VERSION 5.7 ;
  NOWIREEXTENSIONATPIN ON ;
  DIVIDERCHAR "/" ;
  BUSBITCHARS "[]" ;
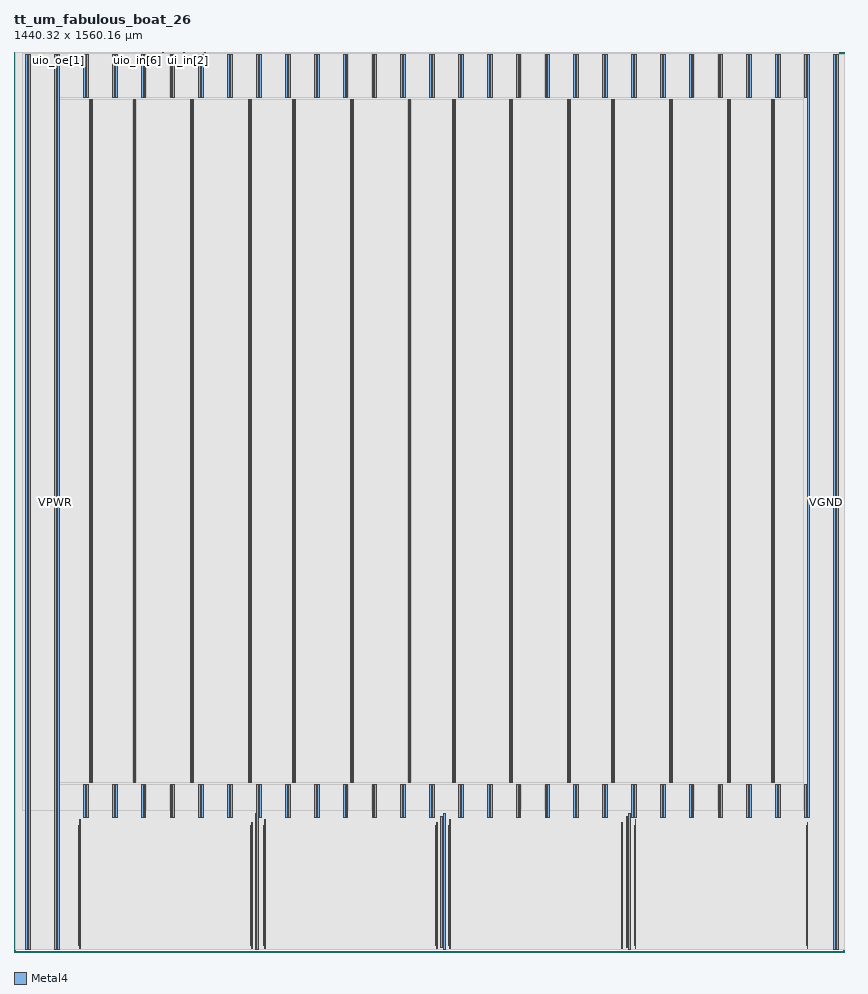
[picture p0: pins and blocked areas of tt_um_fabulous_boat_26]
MACRO tt_um_fabulous_boat_26
  CLASS BLOCK ;
  FOREIGN tt_um_fabulous_boat_26 ;
  ORIGIN 0.000 0.000 ;
  SIZE 1440.320 BY 1560.160 ;
  PIN VGND
    DIRECTION INOUT ;
    USE GROUND ;
    PORT
      LAYER Metal4 ;
        RECT 134.180 1403.360 135.780 1477.840 ;
    END
    PORT
      LAYER Metal4 ;
        RECT 134.180 1144.640 135.780 1403.360 ;
    END
    PORT
      LAYER Metal4 ;
        RECT 134.180 885.920 135.780 1144.640 ;
    END
    PORT
      LAYER Metal4 ;
        RECT 134.180 627.200 135.780 885.920 ;
    END
    PORT
      LAYER Metal4 ;
        RECT 134.180 368.480 135.780 627.200 ;
    END
    PORT
      LAYER Metal4 ;
        RECT 134.180 294.000 135.780 368.480 ;
    END
    PORT
      LAYER Metal4 ;
        RECT 209.780 1403.360 211.380 1477.840 ;
    END
    PORT
      LAYER Metal4 ;
        RECT 309.780 1403.360 311.380 1477.840 ;
    END
    PORT
      LAYER Metal4 ;
        RECT 409.780 1403.360 411.380 1477.840 ;
    END
    PORT
      LAYER Metal4 ;
        RECT 209.780 1144.640 211.380 1403.360 ;
    END
    PORT
      LAYER Metal4 ;
        RECT 309.780 1144.640 311.380 1403.360 ;
    END
    PORT
      LAYER Metal4 ;
        RECT 409.780 1144.640 411.380 1403.360 ;
    END
    PORT
      LAYER Metal4 ;
        RECT 209.780 885.920 211.380 1144.640 ;
    END
    PORT
      LAYER Metal4 ;
        RECT 309.780 885.920 311.380 1144.640 ;
    END
    PORT
      LAYER Metal4 ;
        RECT 409.780 885.920 411.380 1144.640 ;
    END
    PORT
      LAYER Metal4 ;
        RECT 209.780 627.200 211.380 885.920 ;
    END
    PORT
      LAYER Metal4 ;
        RECT 309.780 627.200 311.380 885.920 ;
    END
    PORT
      LAYER Metal4 ;
        RECT 409.780 627.200 411.380 885.920 ;
    END
    PORT
      LAYER Metal4 ;
        RECT 209.780 368.480 211.380 627.200 ;
    END
    PORT
      LAYER Metal4 ;
        RECT 309.780 368.480 311.380 627.200 ;
    END
    PORT
      LAYER Metal4 ;
        RECT 409.780 368.480 411.380 627.200 ;
    END
    PORT
      LAYER Metal4 ;
        RECT 209.780 294.000 211.380 368.480 ;
    END
    PORT
      LAYER Metal4 ;
        RECT 309.780 294.000 311.380 368.480 ;
    END
    PORT
      LAYER Metal4 ;
        RECT 409.780 294.000 411.380 368.480 ;
    END
    PORT
      LAYER Metal4 ;
        RECT 486.420 1403.360 488.020 1477.840 ;
    END
    PORT
      LAYER Metal4 ;
        RECT 586.420 1403.360 588.020 1477.840 ;
    END
    PORT
      LAYER Metal4 ;
        RECT 686.420 1403.360 688.020 1477.840 ;
    END
    PORT
      LAYER Metal4 ;
        RECT 486.420 1144.640 488.020 1403.360 ;
    END
    PORT
      LAYER Metal4 ;
        RECT 586.420 1144.640 588.020 1403.360 ;
    END
    PORT
      LAYER Metal4 ;
        RECT 686.420 1144.640 688.020 1403.360 ;
    END
    PORT
      LAYER Metal4 ;
        RECT 486.420 885.920 488.020 1144.640 ;
    END
    PORT
      LAYER Metal4 ;
        RECT 586.420 885.920 588.020 1144.640 ;
    END
    PORT
      LAYER Metal4 ;
        RECT 686.420 885.920 688.020 1144.640 ;
    END
    PORT
      LAYER Metal4 ;
        RECT 486.420 627.200 488.020 885.920 ;
    END
    PORT
      LAYER Metal4 ;
        RECT 586.420 627.200 588.020 885.920 ;
    END
    PORT
      LAYER Metal4 ;
        RECT 686.420 627.200 688.020 885.920 ;
    END
    PORT
      LAYER Metal4 ;
        RECT 486.420 368.480 488.020 627.200 ;
    END
    PORT
      LAYER Metal4 ;
        RECT 586.420 368.480 588.020 627.200 ;
    END
    PORT
      LAYER Metal4 ;
        RECT 686.420 368.480 688.020 627.200 ;
    END
    PORT
      LAYER Metal4 ;
        RECT 486.420 294.000 488.020 368.480 ;
    END
    PORT
      LAYER Metal4 ;
        RECT 586.420 294.000 588.020 368.480 ;
    END
    PORT
      LAYER Metal4 ;
        RECT 686.420 294.000 688.020 368.480 ;
    END
    PORT
      LAYER Metal4 ;
        RECT 763.060 1403.360 764.660 1477.840 ;
    END
    PORT
      LAYER Metal4 ;
        RECT 863.060 1403.360 864.660 1477.840 ;
    END
    PORT
      LAYER Metal4 ;
        RECT 963.060 1403.360 964.660 1477.840 ;
    END
    PORT
      LAYER Metal4 ;
        RECT 763.060 1144.640 764.660 1403.360 ;
    END
    PORT
      LAYER Metal4 ;
        RECT 863.060 1144.640 864.660 1403.360 ;
    END
    PORT
      LAYER Metal4 ;
        RECT 963.060 1144.640 964.660 1403.360 ;
    END
    PORT
      LAYER Metal4 ;
        RECT 763.060 885.920 764.660 1144.640 ;
    END
    PORT
      LAYER Metal4 ;
        RECT 863.060 885.920 864.660 1144.640 ;
    END
    PORT
      LAYER Metal4 ;
        RECT 963.060 885.920 964.660 1144.640 ;
    END
    PORT
      LAYER Metal4 ;
        RECT 763.060 627.200 764.660 885.920 ;
    END
    PORT
      LAYER Metal4 ;
        RECT 863.060 627.200 864.660 885.920 ;
    END
    PORT
      LAYER Metal4 ;
        RECT 963.060 627.200 964.660 885.920 ;
    END
    PORT
      LAYER Metal4 ;
        RECT 763.060 368.480 764.660 627.200 ;
    END
    PORT
      LAYER Metal4 ;
        RECT 863.060 368.480 864.660 627.200 ;
    END
    PORT
      LAYER Metal4 ;
        RECT 963.060 368.480 964.660 627.200 ;
    END
    PORT
      LAYER Metal4 ;
        RECT 763.060 294.000 764.660 368.480 ;
    END
    PORT
      LAYER Metal4 ;
        RECT 863.060 294.000 864.660 368.480 ;
    END
    PORT
      LAYER Metal4 ;
        RECT 963.060 294.000 964.660 368.480 ;
    END
    PORT
      LAYER Metal4 ;
        RECT 1039.700 1403.360 1041.300 1477.840 ;
    END
    PORT
      LAYER Metal4 ;
        RECT 1139.700 1403.360 1141.300 1477.840 ;
    END
    PORT
      LAYER Metal4 ;
        RECT 1239.700 1403.360 1241.300 1477.840 ;
    END
    PORT
      LAYER Metal4 ;
        RECT 1039.700 1144.640 1041.300 1403.360 ;
    END
    PORT
      LAYER Metal4 ;
        RECT 1139.700 1144.640 1141.300 1403.360 ;
    END
    PORT
      LAYER Metal4 ;
        RECT 1239.700 1144.640 1241.300 1403.360 ;
    END
    PORT
      LAYER Metal4 ;
        RECT 1039.700 885.920 1041.300 1144.640 ;
    END
    PORT
      LAYER Metal4 ;
        RECT 1139.700 885.920 1141.300 1144.640 ;
    END
    PORT
      LAYER Metal4 ;
        RECT 1239.700 885.920 1241.300 1144.640 ;
    END
    PORT
      LAYER Metal4 ;
        RECT 1039.700 627.200 1041.300 885.920 ;
    END
    PORT
      LAYER Metal4 ;
        RECT 1139.700 627.200 1141.300 885.920 ;
    END
    PORT
      LAYER Metal4 ;
        RECT 1239.700 627.200 1241.300 885.920 ;
    END
    PORT
      LAYER Metal4 ;
        RECT 1039.700 368.480 1041.300 627.200 ;
    END
    PORT
      LAYER Metal4 ;
        RECT 1139.700 368.480 1141.300 627.200 ;
    END
    PORT
      LAYER Metal4 ;
        RECT 1239.700 368.480 1241.300 627.200 ;
    END
    PORT
      LAYER Metal4 ;
        RECT 1039.700 294.000 1041.300 368.480 ;
    END
    PORT
      LAYER Metal4 ;
        RECT 1139.700 294.000 1141.300 368.480 ;
    END
    PORT
      LAYER Metal4 ;
        RECT 1239.700 294.000 1241.300 368.480 ;
    END
    PORT
      LAYER Metal4 ;
        RECT 1316.340 1403.360 1317.940 1477.840 ;
    END
    PORT
      LAYER Metal4 ;
        RECT 1316.340 1144.640 1317.940 1403.360 ;
    END
    PORT
      LAYER Metal4 ;
        RECT 1316.340 885.920 1317.940 1144.640 ;
    END
    PORT
      LAYER Metal4 ;
        RECT 1316.340 627.200 1317.940 885.920 ;
    END
    PORT
      LAYER Metal4 ;
        RECT 1316.340 368.480 1317.940 627.200 ;
    END
    PORT
      LAYER Metal4 ;
        RECT 1316.340 294.000 1317.940 368.480 ;
    END
    PORT
      LAYER Metal4 ;
        RECT 25.540 3.620 28.740 1556.540 ;
    END
    PORT
      LAYER Metal4 ;
        RECT 75.540 3.620 78.740 1556.540 ;
    END
    PORT
      LAYER Metal4 ;
        RECT 125.540 233.610 128.740 289.890 ;
    END
    PORT
      LAYER Metal4 ;
        RECT 125.540 1481.950 128.740 1556.540 ;
    END
    PORT
      LAYER Metal4 ;
        RECT 175.540 233.610 178.740 289.890 ;
    END
    PORT
      LAYER Metal4 ;
        RECT 175.540 1481.950 178.740 1556.540 ;
    END
    PORT
      LAYER Metal4 ;
        RECT 225.540 233.610 228.740 289.890 ;
    END
    PORT
      LAYER Metal4 ;
        RECT 225.540 1481.950 228.740 1556.540 ;
    END
    PORT
      LAYER Metal4 ;
        RECT 275.540 233.610 278.740 289.890 ;
    END
    PORT
      LAYER Metal4 ;
        RECT 275.540 1481.950 278.740 1556.540 ;
    END
    PORT
      LAYER Metal4 ;
        RECT 325.540 233.610 328.740 289.890 ;
    END
    PORT
      LAYER Metal4 ;
        RECT 325.540 1481.950 328.740 1556.540 ;
    END
    PORT
      LAYER Metal4 ;
        RECT 375.540 233.610 378.740 289.890 ;
    END
    PORT
      LAYER Metal4 ;
        RECT 375.540 1481.950 378.740 1556.540 ;
    END
    PORT
      LAYER Metal4 ;
        RECT 425.540 233.610 428.740 289.890 ;
    END
    PORT
      LAYER Metal4 ;
        RECT 425.540 1481.950 428.740 1556.540 ;
    END
    PORT
      LAYER Metal4 ;
        RECT 475.540 233.610 478.740 289.890 ;
    END
    PORT
      LAYER Metal4 ;
        RECT 475.540 1481.950 478.740 1556.540 ;
    END
    PORT
      LAYER Metal4 ;
        RECT 525.540 233.610 528.740 289.890 ;
    END
    PORT
      LAYER Metal4 ;
        RECT 525.540 1481.950 528.740 1556.540 ;
    END
    PORT
      LAYER Metal4 ;
        RECT 575.540 233.610 578.740 289.890 ;
    END
    PORT
      LAYER Metal4 ;
        RECT 575.540 1481.950 578.740 1556.540 ;
    END
    PORT
      LAYER Metal4 ;
        RECT 625.540 233.610 628.740 289.890 ;
    END
    PORT
      LAYER Metal4 ;
        RECT 625.540 1481.950 628.740 1556.540 ;
    END
    PORT
      LAYER Metal4 ;
        RECT 675.540 233.610 678.740 289.890 ;
    END
    PORT
      LAYER Metal4 ;
        RECT 675.540 1481.950 678.740 1556.540 ;
    END
    PORT
      LAYER Metal4 ;
        RECT 725.540 233.610 728.740 289.890 ;
    END
    PORT
      LAYER Metal4 ;
        RECT 725.540 1481.950 728.740 1556.540 ;
    END
    PORT
      LAYER Metal4 ;
        RECT 775.540 233.610 778.740 289.890 ;
    END
    PORT
      LAYER Metal4 ;
        RECT 775.540 1481.950 778.740 1556.540 ;
    END
    PORT
      LAYER Metal4 ;
        RECT 825.540 233.610 828.740 289.890 ;
    END
    PORT
      LAYER Metal4 ;
        RECT 825.540 1481.950 828.740 1556.540 ;
    END
    PORT
      LAYER Metal4 ;
        RECT 875.540 233.610 878.740 289.890 ;
    END
    PORT
      LAYER Metal4 ;
        RECT 875.540 1481.950 878.740 1556.540 ;
    END
    PORT
      LAYER Metal4 ;
        RECT 925.540 233.610 928.740 289.890 ;
    END
    PORT
      LAYER Metal4 ;
        RECT 925.540 1481.950 928.740 1556.540 ;
    END
    PORT
      LAYER Metal4 ;
        RECT 975.540 233.610 978.740 289.890 ;
    END
    PORT
      LAYER Metal4 ;
        RECT 975.540 1481.950 978.740 1556.540 ;
    END
    PORT
      LAYER Metal4 ;
        RECT 1025.540 233.610 1028.740 289.890 ;
    END
    PORT
      LAYER Metal4 ;
        RECT 1025.540 1481.950 1028.740 1556.540 ;
    END
    PORT
      LAYER Metal4 ;
        RECT 1075.540 233.610 1078.740 289.890 ;
    END
    PORT
      LAYER Metal4 ;
        RECT 1075.540 1481.950 1078.740 1556.540 ;
    END
    PORT
      LAYER Metal4 ;
        RECT 1125.540 233.610 1128.740 289.890 ;
    END
    PORT
      LAYER Metal4 ;
        RECT 1125.540 1481.950 1128.740 1556.540 ;
    END
    PORT
      LAYER Metal4 ;
        RECT 1175.540 233.610 1178.740 289.890 ;
    END
    PORT
      LAYER Metal4 ;
        RECT 1175.540 1481.950 1178.740 1556.540 ;
    END
    PORT
      LAYER Metal4 ;
        RECT 1225.540 233.610 1228.740 289.890 ;
    END
    PORT
      LAYER Metal4 ;
        RECT 1225.540 1481.950 1228.740 1556.540 ;
    END
    PORT
      LAYER Metal4 ;
        RECT 1275.540 233.610 1278.740 289.890 ;
    END
    PORT
      LAYER Metal4 ;
        RECT 1275.540 1481.950 1278.740 1556.540 ;
    END
    PORT
      LAYER Metal4 ;
        RECT 1325.540 233.610 1328.740 289.890 ;
    END
    PORT
      LAYER Metal4 ;
        RECT 1325.540 1481.950 1328.740 1556.540 ;
    END
    PORT
      LAYER Metal4 ;
        RECT 1375.540 233.610 1378.740 1556.540 ;
    END
    PORT
      LAYER Metal4 ;
        RECT 1425.540 3.620 1428.740 1556.540 ;
    END
    PORT
      LAYER Metal4 ;
        RECT 1373.300 10.615 1374.660 220.100 ;
    END
    PORT
      LAYER Metal4 ;
        RECT 1075.000 10.600 1076.360 220.110 ;
    END
    PORT
      LAYER Metal4 ;
        RECT 1052.300 10.615 1053.660 220.100 ;
    END
    PORT
      LAYER Metal4 ;
        RECT 754.000 10.600 755.360 220.110 ;
    END
    PORT
      LAYER Metal4 ;
        RECT 731.300 10.615 732.660 220.100 ;
    END
    PORT
      LAYER Metal4 ;
        RECT 433.000 10.600 434.360 220.110 ;
    END
    PORT
      LAYER Metal4 ;
        RECT 410.300 10.615 411.660 220.100 ;
    END
    PORT
      LAYER Metal4 ;
        RECT 112.000 10.600 113.360 220.110 ;
    END
    PORT
      LAYER Metal4 ;
        RECT 1066.040 3.620 1069.240 239.420 ;
    END
    PORT
      LAYER Metal4 ;
        RECT 745.160 3.620 748.360 239.420 ;
    END
    PORT
      LAYER Metal4 ;
        RECT 418.360 3.620 419.960 239.420 ;
    END
  END VGND
  PIN VPWR
    DIRECTION INOUT ;
    USE POWER ;
    PORT
      LAYER Metal4 ;
        RECT 130.880 1403.360 132.480 1477.840 ;
    END
    PORT
      LAYER Metal4 ;
        RECT 130.880 1144.640 132.480 1403.360 ;
    END
    PORT
      LAYER Metal4 ;
        RECT 130.880 885.920 132.480 1144.640 ;
    END
    PORT
      LAYER Metal4 ;
        RECT 130.880 627.200 132.480 885.920 ;
    END
    PORT
      LAYER Metal4 ;
        RECT 130.880 368.480 132.480 627.200 ;
    END
    PORT
      LAYER Metal4 ;
        RECT 130.880 294.000 132.480 368.480 ;
    END
    PORT
      LAYER Metal4 ;
        RECT 206.480 1403.360 208.080 1477.840 ;
    END
    PORT
      LAYER Metal4 ;
        RECT 306.480 1403.360 308.080 1477.840 ;
    END
    PORT
      LAYER Metal4 ;
        RECT 406.480 1403.360 408.080 1477.840 ;
    END
    PORT
      LAYER Metal4 ;
        RECT 206.480 1144.640 208.080 1403.360 ;
    END
    PORT
      LAYER Metal4 ;
        RECT 306.480 1144.640 308.080 1403.360 ;
    END
    PORT
      LAYER Metal4 ;
        RECT 406.480 1144.640 408.080 1403.360 ;
    END
    PORT
      LAYER Metal4 ;
        RECT 206.480 885.920 208.080 1144.640 ;
    END
    PORT
      LAYER Metal4 ;
        RECT 306.480 885.920 308.080 1144.640 ;
    END
    PORT
      LAYER Metal4 ;
        RECT 406.480 885.920 408.080 1144.640 ;
    END
    PORT
      LAYER Metal4 ;
        RECT 206.480 627.200 208.080 885.920 ;
    END
    PORT
      LAYER Metal4 ;
        RECT 306.480 627.200 308.080 885.920 ;
    END
    PORT
      LAYER Metal4 ;
        RECT 406.480 627.200 408.080 885.920 ;
    END
    PORT
      LAYER Metal4 ;
        RECT 206.480 368.480 208.080 627.200 ;
    END
    PORT
      LAYER Metal4 ;
        RECT 306.480 368.480 308.080 627.200 ;
    END
    PORT
      LAYER Metal4 ;
        RECT 406.480 368.480 408.080 627.200 ;
    END
    PORT
      LAYER Metal4 ;
        RECT 206.480 294.000 208.080 368.480 ;
    END
    PORT
      LAYER Metal4 ;
        RECT 306.480 294.000 308.080 368.480 ;
    END
    PORT
      LAYER Metal4 ;
        RECT 406.480 294.000 408.080 368.480 ;
    END
    PORT
      LAYER Metal4 ;
        RECT 483.120 1403.360 484.720 1477.840 ;
    END
    PORT
      LAYER Metal4 ;
        RECT 583.120 1403.360 584.720 1477.840 ;
    END
    PORT
      LAYER Metal4 ;
        RECT 683.120 1403.360 684.720 1477.840 ;
    END
    PORT
      LAYER Metal4 ;
        RECT 483.120 1144.640 484.720 1403.360 ;
    END
    PORT
      LAYER Metal4 ;
        RECT 583.120 1144.640 584.720 1403.360 ;
    END
    PORT
      LAYER Metal4 ;
        RECT 683.120 1144.640 684.720 1403.360 ;
    END
    PORT
      LAYER Metal4 ;
        RECT 483.120 885.920 484.720 1144.640 ;
    END
    PORT
      LAYER Metal4 ;
        RECT 583.120 885.920 584.720 1144.640 ;
    END
    PORT
      LAYER Metal4 ;
        RECT 683.120 885.920 684.720 1144.640 ;
    END
    PORT
      LAYER Metal4 ;
        RECT 483.120 627.200 484.720 885.920 ;
    END
    PORT
      LAYER Metal4 ;
        RECT 583.120 627.200 584.720 885.920 ;
    END
    PORT
      LAYER Metal4 ;
        RECT 683.120 627.200 684.720 885.920 ;
    END
    PORT
      LAYER Metal4 ;
        RECT 483.120 368.480 484.720 627.200 ;
    END
    PORT
      LAYER Metal4 ;
        RECT 583.120 368.480 584.720 627.200 ;
    END
    PORT
      LAYER Metal4 ;
        RECT 683.120 368.480 684.720 627.200 ;
    END
    PORT
      LAYER Metal4 ;
        RECT 483.120 294.000 484.720 368.480 ;
    END
    PORT
      LAYER Metal4 ;
        RECT 583.120 294.000 584.720 368.480 ;
    END
    PORT
      LAYER Metal4 ;
        RECT 683.120 294.000 684.720 368.480 ;
    END
    PORT
      LAYER Metal4 ;
        RECT 759.760 1403.360 761.360 1477.840 ;
    END
    PORT
      LAYER Metal4 ;
        RECT 859.760 1403.360 861.360 1477.840 ;
    END
    PORT
      LAYER Metal4 ;
        RECT 959.760 1403.360 961.360 1477.840 ;
    END
    PORT
      LAYER Metal4 ;
        RECT 759.760 1144.640 761.360 1403.360 ;
    END
    PORT
      LAYER Metal4 ;
        RECT 859.760 1144.640 861.360 1403.360 ;
    END
    PORT
      LAYER Metal4 ;
        RECT 959.760 1144.640 961.360 1403.360 ;
    END
    PORT
      LAYER Metal4 ;
        RECT 759.760 885.920 761.360 1144.640 ;
    END
    PORT
      LAYER Metal4 ;
        RECT 859.760 885.920 861.360 1144.640 ;
    END
    PORT
      LAYER Metal4 ;
        RECT 959.760 885.920 961.360 1144.640 ;
    END
    PORT
      LAYER Metal4 ;
        RECT 759.760 627.200 761.360 885.920 ;
    END
    PORT
      LAYER Metal4 ;
        RECT 859.760 627.200 861.360 885.920 ;
    END
    PORT
      LAYER Metal4 ;
        RECT 959.760 627.200 961.360 885.920 ;
    END
    PORT
      LAYER Metal4 ;
        RECT 759.760 368.480 761.360 627.200 ;
    END
    PORT
      LAYER Metal4 ;
        RECT 859.760 368.480 861.360 627.200 ;
    END
    PORT
      LAYER Metal4 ;
        RECT 959.760 368.480 961.360 627.200 ;
    END
    PORT
      LAYER Metal4 ;
        RECT 759.760 294.000 761.360 368.480 ;
    END
    PORT
      LAYER Metal4 ;
        RECT 859.760 294.000 861.360 368.480 ;
    END
    PORT
      LAYER Metal4 ;
        RECT 959.760 294.000 961.360 368.480 ;
    END
    PORT
      LAYER Metal4 ;
        RECT 1036.400 1403.360 1038.000 1477.840 ;
    END
    PORT
      LAYER Metal4 ;
        RECT 1136.400 1403.360 1138.000 1477.840 ;
    END
    PORT
      LAYER Metal4 ;
        RECT 1236.400 1403.360 1238.000 1477.840 ;
    END
    PORT
      LAYER Metal4 ;
        RECT 1036.400 1144.640 1038.000 1403.360 ;
    END
    PORT
      LAYER Metal4 ;
        RECT 1136.400 1144.640 1138.000 1403.360 ;
    END
    PORT
      LAYER Metal4 ;
        RECT 1236.400 1144.640 1238.000 1403.360 ;
    END
    PORT
      LAYER Metal4 ;
        RECT 1036.400 885.920 1038.000 1144.640 ;
    END
    PORT
      LAYER Metal4 ;
        RECT 1136.400 885.920 1138.000 1144.640 ;
    END
    PORT
      LAYER Metal4 ;
        RECT 1236.400 885.920 1238.000 1144.640 ;
    END
    PORT
      LAYER Metal4 ;
        RECT 1036.400 627.200 1038.000 885.920 ;
    END
    PORT
      LAYER Metal4 ;
        RECT 1136.400 627.200 1138.000 885.920 ;
    END
    PORT
      LAYER Metal4 ;
        RECT 1236.400 627.200 1238.000 885.920 ;
    END
    PORT
      LAYER Metal4 ;
        RECT 1036.400 368.480 1038.000 627.200 ;
    END
    PORT
      LAYER Metal4 ;
        RECT 1136.400 368.480 1138.000 627.200 ;
    END
    PORT
      LAYER Metal4 ;
        RECT 1236.400 368.480 1238.000 627.200 ;
    END
    PORT
      LAYER Metal4 ;
        RECT 1036.400 294.000 1038.000 368.480 ;
    END
    PORT
      LAYER Metal4 ;
        RECT 1136.400 294.000 1138.000 368.480 ;
    END
    PORT
      LAYER Metal4 ;
        RECT 1236.400 294.000 1238.000 368.480 ;
    END
    PORT
      LAYER Metal4 ;
        RECT 1313.040 1403.360 1314.640 1477.840 ;
    END
    PORT
      LAYER Metal4 ;
        RECT 1313.040 1144.640 1314.640 1403.360 ;
    END
    PORT
      LAYER Metal4 ;
        RECT 1313.040 885.920 1314.640 1144.640 ;
    END
    PORT
      LAYER Metal4 ;
        RECT 1313.040 627.200 1314.640 885.920 ;
    END
    PORT
      LAYER Metal4 ;
        RECT 1313.040 368.480 1314.640 627.200 ;
    END
    PORT
      LAYER Metal4 ;
        RECT 1313.040 294.000 1314.640 368.480 ;
    END
    PORT
      LAYER Metal4 ;
        RECT 20.640 3.620 23.840 1556.540 ;
    END
    PORT
      LAYER Metal4 ;
        RECT 70.640 3.620 73.840 1556.540 ;
    END
    PORT
      LAYER Metal4 ;
        RECT 120.640 233.610 123.840 289.890 ;
    END
    PORT
      LAYER Metal4 ;
        RECT 120.640 1481.950 123.840 1556.540 ;
    END
    PORT
      LAYER Metal4 ;
        RECT 170.640 233.610 173.840 289.890 ;
    END
    PORT
      LAYER Metal4 ;
        RECT 170.640 1481.950 173.840 1556.540 ;
    END
    PORT
      LAYER Metal4 ;
        RECT 220.640 233.610 223.840 289.890 ;
    END
    PORT
      LAYER Metal4 ;
        RECT 220.640 1481.950 223.840 1556.540 ;
    END
    PORT
      LAYER Metal4 ;
        RECT 270.640 233.610 273.840 289.890 ;
    END
    PORT
      LAYER Metal4 ;
        RECT 270.640 1481.950 273.840 1556.540 ;
    END
    PORT
      LAYER Metal4 ;
        RECT 320.640 233.610 323.840 289.890 ;
    END
    PORT
      LAYER Metal4 ;
        RECT 320.640 1481.950 323.840 1556.540 ;
    END
    PORT
      LAYER Metal4 ;
        RECT 370.640 233.610 373.840 289.890 ;
    END
    PORT
      LAYER Metal4 ;
        RECT 370.640 1481.950 373.840 1556.540 ;
    END
    PORT
      LAYER Metal4 ;
        RECT 420.640 3.620 423.840 289.890 ;
    END
    PORT
      LAYER Metal4 ;
        RECT 420.640 1481.950 423.840 1556.540 ;
    END
    PORT
      LAYER Metal4 ;
        RECT 470.640 233.610 473.840 289.890 ;
    END
    PORT
      LAYER Metal4 ;
        RECT 470.640 1481.950 473.840 1556.540 ;
    END
    PORT
      LAYER Metal4 ;
        RECT 520.640 233.610 523.840 289.890 ;
    END
    PORT
      LAYER Metal4 ;
        RECT 520.640 1481.950 523.840 1556.540 ;
    END
    PORT
      LAYER Metal4 ;
        RECT 570.640 233.610 573.840 289.890 ;
    END
    PORT
      LAYER Metal4 ;
        RECT 570.640 1481.950 573.840 1556.540 ;
    END
    PORT
      LAYER Metal4 ;
        RECT 620.640 233.610 623.840 289.890 ;
    END
    PORT
      LAYER Metal4 ;
        RECT 620.640 1481.950 623.840 1556.540 ;
    END
    PORT
      LAYER Metal4 ;
        RECT 670.640 233.610 673.840 289.890 ;
    END
    PORT
      LAYER Metal4 ;
        RECT 670.640 1481.950 673.840 1556.540 ;
    END
    PORT
      LAYER Metal4 ;
        RECT 720.640 233.610 723.840 289.890 ;
    END
    PORT
      LAYER Metal4 ;
        RECT 720.640 1481.950 723.840 1556.540 ;
    END
    PORT
      LAYER Metal4 ;
        RECT 770.640 233.610 773.840 289.890 ;
    END
    PORT
      LAYER Metal4 ;
        RECT 770.640 1481.950 773.840 1556.540 ;
    END
    PORT
      LAYER Metal4 ;
        RECT 820.640 233.610 823.840 289.890 ;
    END
    PORT
      LAYER Metal4 ;
        RECT 820.640 1481.950 823.840 1556.540 ;
    END
    PORT
      LAYER Metal4 ;
        RECT 870.640 233.610 873.840 289.890 ;
    END
    PORT
      LAYER Metal4 ;
        RECT 870.640 1481.950 873.840 1556.540 ;
    END
    PORT
      LAYER Metal4 ;
        RECT 920.640 233.610 923.840 289.890 ;
    END
    PORT
      LAYER Metal4 ;
        RECT 920.640 1481.950 923.840 1556.540 ;
    END
    PORT
      LAYER Metal4 ;
        RECT 970.640 233.610 973.840 289.890 ;
    END
    PORT
      LAYER Metal4 ;
        RECT 970.640 1481.950 973.840 1556.540 ;
    END
    PORT
      LAYER Metal4 ;
        RECT 1020.640 233.610 1023.840 289.890 ;
    END
    PORT
      LAYER Metal4 ;
        RECT 1020.640 1481.950 1023.840 1556.540 ;
    END
    PORT
      LAYER Metal4 ;
        RECT 1070.640 233.610 1073.840 289.890 ;
    END
    PORT
      LAYER Metal4 ;
        RECT 1070.640 1481.950 1073.840 1556.540 ;
    END
    PORT
      LAYER Metal4 ;
        RECT 1120.640 233.610 1123.840 289.890 ;
    END
    PORT
      LAYER Metal4 ;
        RECT 1120.640 1481.950 1123.840 1556.540 ;
    END
    PORT
      LAYER Metal4 ;
        RECT 1170.640 233.610 1173.840 289.890 ;
    END
    PORT
      LAYER Metal4 ;
        RECT 1170.640 1481.950 1173.840 1556.540 ;
    END
    PORT
      LAYER Metal4 ;
        RECT 1220.640 233.610 1223.840 289.890 ;
    END
    PORT
      LAYER Metal4 ;
        RECT 1220.640 1481.950 1223.840 1556.540 ;
    END
    PORT
      LAYER Metal4 ;
        RECT 1270.640 233.610 1273.840 289.890 ;
    END
    PORT
      LAYER Metal4 ;
        RECT 1270.640 1481.950 1273.840 1556.540 ;
    END
    PORT
      LAYER Metal4 ;
        RECT 1320.640 233.610 1323.840 289.890 ;
    END
    PORT
      LAYER Metal4 ;
        RECT 1320.640 1481.950 1323.840 1556.540 ;
    END
    PORT
      LAYER Metal4 ;
        RECT 1370.640 233.610 1373.840 289.890 ;
    END
    PORT
      LAYER Metal4 ;
        RECT 1370.640 1481.950 1373.840 1556.540 ;
    END
    PORT
      LAYER Metal4 ;
        RECT 1420.640 3.620 1423.840 1556.540 ;
    END
    PORT
      LAYER Metal4 ;
        RECT 1374.940 6.920 1376.300 224.540 ;
    END
    PORT
      LAYER Metal4 ;
        RECT 1076.640 6.920 1078.000 228.850 ;
    END
    PORT
      LAYER Metal4 ;
        RECT 1053.940 6.920 1055.300 224.540 ;
    END
    PORT
      LAYER Metal4 ;
        RECT 755.640 6.920 757.000 228.850 ;
    END
    PORT
      LAYER Metal4 ;
        RECT 732.940 6.920 734.300 224.540 ;
    END
    PORT
      LAYER Metal4 ;
        RECT 434.640 6.920 436.000 228.850 ;
    END
    PORT
      LAYER Metal4 ;
        RECT 411.940 6.920 413.300 224.540 ;
    END
    PORT
      LAYER Metal4 ;
        RECT 113.640 6.920 115.000 228.850 ;
    END
    PORT
      LAYER Metal4 ;
        RECT 1061.000 7.540 1064.200 235.500 ;
    END
    PORT
      LAYER Metal4 ;
        RECT 740.120 7.540 743.320 235.500 ;
    END
  END VPWR
  PIN clk
    DIRECTION INPUT ;
    USE SIGNAL ;
    ANTENNAGATEAREA 4.116000 ;
    ANTENNADIFFAREA 0.877000 ;
    PORT
      LAYER Metal4 ;
        RECT 331.090 1559.160 331.390 1560.160 ;
    END
  END clk
  PIN ena
    DIRECTION INPUT ;
    USE SIGNAL ;
    PORT
      LAYER Metal4 ;
        RECT 338.370 1559.160 338.670 1560.160 ;
    END
  END ena
  PIN rst_n
    DIRECTION INPUT ;
    USE SIGNAL ;
    ANTENNAGATEAREA 0.666400 ;
    ANTENNADIFFAREA 0.438500 ;
    PORT
      LAYER Metal4 ;
        RECT 323.810 1559.160 324.110 1560.160 ;
    END
  END rst_n
  PIN ui_in[0]
    DIRECTION INPUT ;
    USE SIGNAL ;
    ANTENNAGATEAREA 0.666400 ;
    ANTENNADIFFAREA 0.438500 ;
    PORT
      LAYER Metal4 ;
        RECT 316.530 1559.160 316.830 1560.160 ;
    END
  END ui_in[0]
  PIN ui_in[1]
    DIRECTION INPUT ;
    USE SIGNAL ;
    ANTENNAGATEAREA 0.666400 ;
    ANTENNADIFFAREA 0.438500 ;
    PORT
      LAYER Metal4 ;
        RECT 309.250 1559.160 309.550 1560.160 ;
    END
  END ui_in[1]
  PIN ui_in[2]
    DIRECTION INPUT ;
    USE SIGNAL ;
    ANTENNAGATEAREA 1.764000 ;
    ANTENNADIFFAREA 0.438500 ;
    PORT
      LAYER Metal4 ;
        RECT 301.970 1559.160 302.270 1560.160 ;
    END
  END ui_in[2]
  PIN ui_in[3]
    DIRECTION INPUT ;
    USE SIGNAL ;
    ANTENNAGATEAREA 1.764000 ;
    ANTENNADIFFAREA 0.438500 ;
    PORT
      LAYER Metal4 ;
        RECT 294.690 1559.160 294.990 1560.160 ;
    END
  END ui_in[3]
  PIN ui_in[4]
    DIRECTION INPUT ;
    USE SIGNAL ;
    ANTENNAGATEAREA 0.588000 ;
    ANTENNADIFFAREA 0.438500 ;
    PORT
      LAYER Metal4 ;
        RECT 287.410 1559.160 287.710 1560.160 ;
    END
  END ui_in[4]
  PIN ui_in[5]
    DIRECTION INPUT ;
    USE SIGNAL ;
    ANTENNAGATEAREA 0.588000 ;
    ANTENNADIFFAREA 0.438500 ;
    PORT
      LAYER Metal4 ;
        RECT 280.130 1559.160 280.430 1560.160 ;
    END
  END ui_in[5]
  PIN ui_in[6]
    DIRECTION INPUT ;
    USE SIGNAL ;
    ANTENNAGATEAREA 1.764000 ;
    ANTENNADIFFAREA 0.438500 ;
    PORT
      LAYER Metal4 ;
        RECT 272.850 1559.160 273.150 1560.160 ;
    END
  END ui_in[6]
  PIN ui_in[7]
    DIRECTION INPUT ;
    USE SIGNAL ;
    ANTENNAGATEAREA 1.764000 ;
    ANTENNADIFFAREA 0.438500 ;
    PORT
      LAYER Metal4 ;
        RECT 265.570 1559.160 265.870 1560.160 ;
    END
  END ui_in[7]
  PIN uio_in[0]
    DIRECTION INPUT ;
    USE SIGNAL ;
    ANTENNAGATEAREA 2.665600 ;
    ANTENNADIFFAREA 0.438500 ;
    PORT
      LAYER Metal4 ;
        RECT 258.290 1559.160 258.590 1560.160 ;
    END
  END uio_in[0]
  PIN uio_in[1]
    DIRECTION INPUT ;
    USE SIGNAL ;
    ANTENNAGATEAREA 1.332800 ;
    ANTENNADIFFAREA 0.438500 ;
    PORT
      LAYER Metal4 ;
        RECT 251.010 1559.160 251.310 1560.160 ;
    END
  END uio_in[1]
  PIN uio_in[2]
    DIRECTION INPUT ;
    USE SIGNAL ;
    ANTENNAGATEAREA 1.332800 ;
    ANTENNADIFFAREA 0.438500 ;
    PORT
      LAYER Metal4 ;
        RECT 243.730 1559.160 244.030 1560.160 ;
    END
  END uio_in[2]
  PIN uio_in[3]
    DIRECTION INPUT ;
    USE SIGNAL ;
    ANTENNAGATEAREA 1.332800 ;
    ANTENNADIFFAREA 0.438500 ;
    PORT
      LAYER Metal4 ;
        RECT 236.450 1559.160 236.750 1560.160 ;
    END
  END uio_in[3]
  PIN uio_in[4]
    DIRECTION INPUT ;
    USE SIGNAL ;
    ANTENNAGATEAREA 0.666400 ;
    ANTENNADIFFAREA 0.438500 ;
    PORT
      LAYER Metal4 ;
        RECT 229.170 1559.160 229.470 1560.160 ;
    END
  END uio_in[4]
  PIN uio_in[5]
    DIRECTION INPUT ;
    USE SIGNAL ;
    ANTENNAGATEAREA 0.666400 ;
    ANTENNADIFFAREA 0.438500 ;
    PORT
      LAYER Metal4 ;
        RECT 221.890 1559.160 222.190 1560.160 ;
    END
  END uio_in[5]
  PIN uio_in[6]
    DIRECTION INPUT ;
    USE SIGNAL ;
    ANTENNAGATEAREA 0.666400 ;
    ANTENNADIFFAREA 0.438500 ;
    PORT
      LAYER Metal4 ;
        RECT 214.610 1559.160 214.910 1560.160 ;
    END
  END uio_in[6]
  PIN uio_in[7]
    DIRECTION INPUT ;
    USE SIGNAL ;
    ANTENNAGATEAREA 0.666400 ;
    ANTENNADIFFAREA 0.438500 ;
    PORT
      LAYER Metal4 ;
        RECT 207.330 1559.160 207.630 1560.160 ;
    END
  END uio_in[7]
  PIN uio_oe[0]
    DIRECTION OUTPUT ;
    USE SIGNAL ;
    ANTENNADIFFAREA 1.676100 ;
    PORT
      LAYER Metal4 ;
        RECT 83.570 1559.160 83.870 1560.160 ;
    END
  END uio_oe[0]
  PIN uio_oe[1]
    DIRECTION OUTPUT ;
    USE SIGNAL ;
    ANTENNADIFFAREA 4.806500 ;
    PORT
      LAYER Metal4 ;
        RECT 76.290 1559.160 76.590 1560.160 ;
    END
  END uio_oe[1]
  PIN uio_oe[2]
    DIRECTION OUTPUT ;
    USE SIGNAL ;
    ANTENNADIFFAREA 4.806500 ;
    PORT
      LAYER Metal4 ;
        RECT 69.010 1559.160 69.310 1560.160 ;
    END
  END uio_oe[2]
  PIN uio_oe[3]
    DIRECTION OUTPUT ;
    USE SIGNAL ;
    ANTENNADIFFAREA 4.806500 ;
    PORT
      LAYER Metal4 ;
        RECT 61.730 1559.160 62.030 1560.160 ;
    END
  END uio_oe[3]
  PIN uio_oe[4]
    DIRECTION OUTPUT ;
    USE SIGNAL ;
    ANTENNADIFFAREA 4.806500 ;
    PORT
      LAYER Metal4 ;
        RECT 54.450 1559.160 54.750 1560.160 ;
    END
  END uio_oe[4]
  PIN uio_oe[5]
    DIRECTION OUTPUT ;
    USE SIGNAL ;
    ANTENNADIFFAREA 4.806500 ;
    PORT
      LAYER Metal4 ;
        RECT 47.170 1559.160 47.470 1560.160 ;
    END
  END uio_oe[5]
  PIN uio_oe[6]
    DIRECTION OUTPUT ;
    USE SIGNAL ;
    ANTENNADIFFAREA 4.806500 ;
    PORT
      LAYER Metal4 ;
        RECT 39.890 1559.160 40.190 1560.160 ;
    END
  END uio_oe[6]
  PIN uio_oe[7]
    DIRECTION OUTPUT ;
    USE SIGNAL ;
    ANTENNADIFFAREA 4.806500 ;
    PORT
      LAYER Metal4 ;
        RECT 32.610 1559.160 32.910 1560.160 ;
    END
  END uio_oe[7]
  PIN uio_out[0]
    DIRECTION OUTPUT ;
    USE SIGNAL ;
    ANTENNADIFFAREA 1.676100 ;
    PORT
      LAYER Metal4 ;
        RECT 141.810 1559.160 142.110 1560.160 ;
    END
  END uio_out[0]
  PIN uio_out[1]
    DIRECTION OUTPUT ;
    USE SIGNAL ;
    ANTENNADIFFAREA 1.676100 ;
    PORT
      LAYER Metal4 ;
        RECT 134.530 1559.160 134.830 1560.160 ;
    END
  END uio_out[1]
  PIN uio_out[2]
    DIRECTION OUTPUT ;
    USE SIGNAL ;
    ANTENNADIFFAREA 1.676100 ;
    PORT
      LAYER Metal4 ;
        RECT 127.250 1559.160 127.550 1560.160 ;
    END
  END uio_out[2]
  PIN uio_out[3]
    DIRECTION OUTPUT ;
    USE SIGNAL ;
    ANTENNADIFFAREA 4.806500 ;
    PORT
      LAYER Metal4 ;
        RECT 119.970 1559.160 120.270 1560.160 ;
    END
  END uio_out[3]
  PIN uio_out[4]
    DIRECTION OUTPUT ;
    USE SIGNAL ;
    ANTENNADIFFAREA 4.806500 ;
    PORT
      LAYER Metal4 ;
        RECT 112.690 1559.160 112.990 1560.160 ;
    END
  END uio_out[4]
  PIN uio_out[5]
    DIRECTION OUTPUT ;
    USE SIGNAL ;
    ANTENNADIFFAREA 4.806500 ;
    PORT
      LAYER Metal4 ;
        RECT 105.410 1559.160 105.710 1560.160 ;
    END
  END uio_out[5]
  PIN uio_out[6]
    DIRECTION OUTPUT ;
    USE SIGNAL ;
    ANTENNADIFFAREA 4.806500 ;
    PORT
      LAYER Metal4 ;
        RECT 98.130 1559.160 98.430 1560.160 ;
    END
  END uio_out[6]
  PIN uio_out[7]
    DIRECTION OUTPUT ;
    USE SIGNAL ;
    ANTENNADIFFAREA 4.806500 ;
    PORT
      LAYER Metal4 ;
        RECT 90.850 1559.160 91.150 1560.160 ;
    END
  END uio_out[7]
  PIN uo_out[0]
    DIRECTION OUTPUT ;
    USE SIGNAL ;
    ANTENNADIFFAREA 4.806500 ;
    PORT
      LAYER Metal4 ;
        RECT 200.050 1559.160 200.350 1560.160 ;
    END
  END uo_out[0]
  PIN uo_out[1]
    DIRECTION OUTPUT ;
    USE SIGNAL ;
    ANTENNADIFFAREA 4.806500 ;
    PORT
      LAYER Metal4 ;
        RECT 192.770 1559.160 193.070 1560.160 ;
    END
  END uo_out[1]
  PIN uo_out[2]
    DIRECTION OUTPUT ;
    USE SIGNAL ;
    ANTENNADIFFAREA 4.806500 ;
    PORT
      LAYER Metal4 ;
        RECT 185.490 1559.160 185.790 1560.160 ;
    END
  END uo_out[2]
  PIN uo_out[3]
    DIRECTION OUTPUT ;
    USE SIGNAL ;
    ANTENNADIFFAREA 4.806500 ;
    PORT
      LAYER Metal4 ;
        RECT 178.210 1559.160 178.510 1560.160 ;
    END
  END uo_out[3]
  PIN uo_out[4]
    DIRECTION OUTPUT ;
    USE SIGNAL ;
    ANTENNADIFFAREA 4.806500 ;
    PORT
      LAYER Metal4 ;
        RECT 170.930 1559.160 171.230 1560.160 ;
    END
  END uo_out[4]
  PIN uo_out[5]
    DIRECTION OUTPUT ;
    USE SIGNAL ;
    ANTENNADIFFAREA 4.806500 ;
    PORT
      LAYER Metal4 ;
        RECT 163.650 1559.160 163.950 1560.160 ;
    END
  END uo_out[5]
  PIN uo_out[6]
    DIRECTION OUTPUT ;
    USE SIGNAL ;
    ANTENNADIFFAREA 4.806500 ;
    PORT
      LAYER Metal4 ;
        RECT 156.370 1559.160 156.670 1560.160 ;
    END
  END uo_out[6]
  PIN uo_out[7]
    DIRECTION OUTPUT ;
    USE SIGNAL ;
    ANTENNADIFFAREA 4.806500 ;
    PORT
      LAYER Metal4 ;
        RECT 149.090 1559.160 149.390 1560.160 ;
    END
  END uo_out[7]
  OBS
      LAYER Pwell ;
        RECT 1.810 1554.470 1440.190 1556.670 ;
      LAYER Nwell ;
        RECT 1.810 1550.170 1440.190 1554.470 ;
      LAYER Pwell ;
        RECT 1.810 1546.630 1440.190 1550.170 ;
      LAYER Nwell ;
        RECT 1.810 1542.330 1440.190 1546.630 ;
      LAYER Pwell ;
        RECT 1.810 1538.790 1440.190 1542.330 ;
      LAYER Nwell ;
        RECT 1.810 1534.490 1440.190 1538.790 ;
      LAYER Pwell ;
        RECT 1.810 1530.950 1440.190 1534.490 ;
      LAYER Nwell ;
        RECT 1.810 1526.650 1440.190 1530.950 ;
      LAYER Pwell ;
        RECT 1.810 1523.110 1440.190 1526.650 ;
      LAYER Nwell ;
        RECT 1.810 1518.810 1440.190 1523.110 ;
      LAYER Pwell ;
        RECT 1.810 1515.270 1440.190 1518.810 ;
      LAYER Nwell ;
        RECT 1.810 1510.970 1440.190 1515.270 ;
      LAYER Pwell ;
        RECT 1.810 1507.430 1440.190 1510.970 ;
      LAYER Nwell ;
        RECT 1.810 1503.130 1440.190 1507.430 ;
      LAYER Pwell ;
        RECT 1.810 1499.590 1440.190 1503.130 ;
      LAYER Nwell ;
        RECT 1.810 1495.290 1440.190 1499.590 ;
      LAYER Pwell ;
        RECT 1.810 1491.750 1440.190 1495.290 ;
      LAYER Nwell ;
        RECT 1.810 1487.450 1440.190 1491.750 ;
      LAYER Pwell ;
        RECT 1.810 1485.250 1440.190 1487.450 ;
        RECT 1.810 1483.910 107.950 1485.250 ;
      LAYER Nwell ;
        RECT 107.950 1483.910 1440.190 1485.250 ;
        RECT 1.810 1479.610 1440.190 1483.910 ;
      LAYER Pwell ;
        RECT 1.810 1476.070 107.950 1479.610 ;
      LAYER Nwell ;
        RECT 107.950 1476.070 1440.190 1479.610 ;
        RECT 1.810 1471.770 1440.190 1476.070 ;
      LAYER Pwell ;
        RECT 1.810 1468.230 107.950 1471.770 ;
      LAYER Nwell ;
        RECT 107.950 1468.230 1440.190 1471.770 ;
        RECT 1.810 1463.930 1440.190 1468.230 ;
      LAYER Pwell ;
        RECT 1.810 1460.390 107.950 1463.930 ;
      LAYER Nwell ;
        RECT 107.950 1460.390 1440.190 1463.930 ;
        RECT 1.810 1456.090 1440.190 1460.390 ;
      LAYER Pwell ;
        RECT 1.810 1452.550 107.950 1456.090 ;
      LAYER Nwell ;
        RECT 107.950 1452.550 1440.190 1456.090 ;
        RECT 1.810 1448.250 1440.190 1452.550 ;
      LAYER Pwell ;
        RECT 1.810 1444.710 107.950 1448.250 ;
      LAYER Nwell ;
        RECT 107.950 1444.710 1440.190 1448.250 ;
        RECT 1.810 1440.410 1440.190 1444.710 ;
      LAYER Pwell ;
        RECT 1.810 1436.870 107.950 1440.410 ;
      LAYER Nwell ;
        RECT 107.950 1436.870 1440.190 1440.410 ;
        RECT 1.810 1432.570 1440.190 1436.870 ;
      LAYER Pwell ;
        RECT 1.810 1429.030 107.950 1432.570 ;
      LAYER Nwell ;
        RECT 107.950 1429.030 1440.190 1432.570 ;
        RECT 1.810 1424.730 1440.190 1429.030 ;
      LAYER Pwell ;
        RECT 1.810 1421.190 107.950 1424.730 ;
      LAYER Nwell ;
        RECT 107.950 1421.190 1440.190 1424.730 ;
        RECT 1.810 1416.890 1440.190 1421.190 ;
      LAYER Pwell ;
        RECT 1.810 1413.350 107.950 1416.890 ;
      LAYER Nwell ;
        RECT 107.950 1413.350 1440.190 1416.890 ;
        RECT 1.810 1409.050 1440.190 1413.350 ;
      LAYER Pwell ;
        RECT 1.810 1405.510 107.950 1409.050 ;
      LAYER Nwell ;
        RECT 107.950 1405.510 1440.190 1409.050 ;
        RECT 1.810 1401.210 1440.190 1405.510 ;
      LAYER Pwell ;
        RECT 1.810 1397.670 107.950 1401.210 ;
      LAYER Nwell ;
        RECT 107.950 1397.670 1440.190 1401.210 ;
        RECT 1.810 1393.370 1440.190 1397.670 ;
      LAYER Pwell ;
        RECT 1.810 1389.830 107.950 1393.370 ;
      LAYER Nwell ;
        RECT 107.950 1389.830 1440.190 1393.370 ;
        RECT 1.810 1385.530 1440.190 1389.830 ;
      LAYER Pwell ;
        RECT 1.810 1381.990 107.950 1385.530 ;
      LAYER Nwell ;
        RECT 107.950 1381.990 1440.190 1385.530 ;
        RECT 1.810 1377.690 1440.190 1381.990 ;
      LAYER Pwell ;
        RECT 1.810 1374.150 107.950 1377.690 ;
      LAYER Nwell ;
        RECT 107.950 1374.150 1440.190 1377.690 ;
        RECT 1.810 1369.850 1440.190 1374.150 ;
      LAYER Pwell ;
        RECT 1.810 1366.310 107.950 1369.850 ;
      LAYER Nwell ;
        RECT 107.950 1366.310 1440.190 1369.850 ;
        RECT 1.810 1362.010 1440.190 1366.310 ;
      LAYER Pwell ;
        RECT 1.810 1358.470 107.950 1362.010 ;
      LAYER Nwell ;
        RECT 107.950 1358.470 1440.190 1362.010 ;
        RECT 1.810 1354.170 1440.190 1358.470 ;
      LAYER Pwell ;
        RECT 1.810 1350.630 107.950 1354.170 ;
      LAYER Nwell ;
        RECT 107.950 1350.630 1440.190 1354.170 ;
        RECT 1.810 1346.330 1440.190 1350.630 ;
      LAYER Pwell ;
        RECT 1.810 1342.790 107.950 1346.330 ;
      LAYER Nwell ;
        RECT 107.950 1342.790 1440.190 1346.330 ;
        RECT 1.810 1338.490 1440.190 1342.790 ;
      LAYER Pwell ;
        RECT 1.810 1334.950 107.950 1338.490 ;
      LAYER Nwell ;
        RECT 107.950 1334.950 1440.190 1338.490 ;
        RECT 1.810 1330.650 1440.190 1334.950 ;
      LAYER Pwell ;
        RECT 1.810 1327.110 107.950 1330.650 ;
      LAYER Nwell ;
        RECT 107.950 1327.110 1440.190 1330.650 ;
        RECT 1.810 1322.810 1440.190 1327.110 ;
      LAYER Pwell ;
        RECT 1.810 1319.270 107.950 1322.810 ;
      LAYER Nwell ;
        RECT 107.950 1319.270 1440.190 1322.810 ;
        RECT 1.810 1314.970 1440.190 1319.270 ;
      LAYER Pwell ;
        RECT 1.810 1311.430 107.950 1314.970 ;
      LAYER Nwell ;
        RECT 107.950 1311.430 1440.190 1314.970 ;
        RECT 1.810 1307.130 1440.190 1311.430 ;
      LAYER Pwell ;
        RECT 1.810 1303.590 107.950 1307.130 ;
      LAYER Nwell ;
        RECT 107.950 1303.590 1440.190 1307.130 ;
        RECT 1.810 1299.290 1440.190 1303.590 ;
      LAYER Pwell ;
        RECT 1.810 1295.750 107.950 1299.290 ;
      LAYER Nwell ;
        RECT 107.950 1295.750 1440.190 1299.290 ;
        RECT 1.810 1291.450 1440.190 1295.750 ;
      LAYER Pwell ;
        RECT 1.810 1287.910 107.950 1291.450 ;
      LAYER Nwell ;
        RECT 107.950 1287.910 1440.190 1291.450 ;
        RECT 1.810 1283.610 1440.190 1287.910 ;
      LAYER Pwell ;
        RECT 1.810 1280.070 107.950 1283.610 ;
      LAYER Nwell ;
        RECT 107.950 1280.070 1440.190 1283.610 ;
        RECT 1.810 1275.770 1440.190 1280.070 ;
      LAYER Pwell ;
        RECT 1.810 1272.230 107.950 1275.770 ;
      LAYER Nwell ;
        RECT 107.950 1272.230 1440.190 1275.770 ;
        RECT 1.810 1267.930 1440.190 1272.230 ;
      LAYER Pwell ;
        RECT 1.810 1264.390 107.950 1267.930 ;
      LAYER Nwell ;
        RECT 107.950 1264.390 1440.190 1267.930 ;
        RECT 1.810 1260.090 1440.190 1264.390 ;
      LAYER Pwell ;
        RECT 1.810 1256.550 107.950 1260.090 ;
      LAYER Nwell ;
        RECT 107.950 1256.550 1440.190 1260.090 ;
        RECT 1.810 1252.250 1440.190 1256.550 ;
      LAYER Pwell ;
        RECT 1.810 1248.710 107.950 1252.250 ;
      LAYER Nwell ;
        RECT 107.950 1248.710 1440.190 1252.250 ;
        RECT 1.810 1244.410 1440.190 1248.710 ;
      LAYER Pwell ;
        RECT 1.810 1240.870 107.950 1244.410 ;
      LAYER Nwell ;
        RECT 107.950 1240.870 1440.190 1244.410 ;
        RECT 1.810 1236.570 1440.190 1240.870 ;
      LAYER Pwell ;
        RECT 1.810 1233.030 107.950 1236.570 ;
      LAYER Nwell ;
        RECT 107.950 1233.030 1440.190 1236.570 ;
        RECT 1.810 1228.730 1440.190 1233.030 ;
      LAYER Pwell ;
        RECT 1.810 1225.190 107.950 1228.730 ;
      LAYER Nwell ;
        RECT 107.950 1225.190 1440.190 1228.730 ;
        RECT 1.810 1220.890 1440.190 1225.190 ;
      LAYER Pwell ;
        RECT 1.810 1217.350 107.950 1220.890 ;
      LAYER Nwell ;
        RECT 107.950 1217.350 1440.190 1220.890 ;
        RECT 1.810 1213.050 1440.190 1217.350 ;
      LAYER Pwell ;
        RECT 1.810 1209.510 107.950 1213.050 ;
      LAYER Nwell ;
        RECT 107.950 1209.510 1440.190 1213.050 ;
        RECT 1.810 1205.210 1440.190 1209.510 ;
      LAYER Pwell ;
        RECT 1.810 1201.670 107.950 1205.210 ;
      LAYER Nwell ;
        RECT 107.950 1201.670 1440.190 1205.210 ;
        RECT 1.810 1197.370 1440.190 1201.670 ;
      LAYER Pwell ;
        RECT 1.810 1193.830 107.950 1197.370 ;
      LAYER Nwell ;
        RECT 107.950 1193.830 1440.190 1197.370 ;
        RECT 1.810 1189.530 1440.190 1193.830 ;
      LAYER Pwell ;
        RECT 1.810 1185.990 107.950 1189.530 ;
      LAYER Nwell ;
        RECT 107.950 1185.990 1440.190 1189.530 ;
        RECT 1.810 1181.690 1440.190 1185.990 ;
      LAYER Pwell ;
        RECT 1.810 1178.150 107.950 1181.690 ;
      LAYER Nwell ;
        RECT 107.950 1178.150 1440.190 1181.690 ;
        RECT 1.810 1173.850 1440.190 1178.150 ;
      LAYER Pwell ;
        RECT 1.810 1170.310 107.950 1173.850 ;
      LAYER Nwell ;
        RECT 107.950 1170.310 1440.190 1173.850 ;
        RECT 1.810 1166.010 1440.190 1170.310 ;
      LAYER Pwell ;
        RECT 1.810 1162.470 107.950 1166.010 ;
      LAYER Nwell ;
        RECT 107.950 1162.470 1440.190 1166.010 ;
        RECT 1.810 1158.170 1440.190 1162.470 ;
      LAYER Pwell ;
        RECT 1.810 1154.630 107.950 1158.170 ;
      LAYER Nwell ;
        RECT 107.950 1154.630 1440.190 1158.170 ;
        RECT 1.810 1150.330 1440.190 1154.630 ;
      LAYER Pwell ;
        RECT 1.810 1146.790 107.950 1150.330 ;
      LAYER Nwell ;
        RECT 107.950 1146.790 1440.190 1150.330 ;
        RECT 1.810 1142.490 1440.190 1146.790 ;
      LAYER Pwell ;
        RECT 1.810 1138.950 107.950 1142.490 ;
      LAYER Nwell ;
        RECT 107.950 1138.950 1440.190 1142.490 ;
        RECT 1.810 1134.650 1440.190 1138.950 ;
      LAYER Pwell ;
        RECT 1.810 1131.110 107.950 1134.650 ;
      LAYER Nwell ;
        RECT 107.950 1131.110 1440.190 1134.650 ;
        RECT 1.810 1126.810 1440.190 1131.110 ;
      LAYER Pwell ;
        RECT 1.810 1123.270 107.950 1126.810 ;
      LAYER Nwell ;
        RECT 107.950 1123.270 1440.190 1126.810 ;
        RECT 1.810 1118.970 1440.190 1123.270 ;
      LAYER Pwell ;
        RECT 1.810 1115.430 107.950 1118.970 ;
      LAYER Nwell ;
        RECT 107.950 1115.430 1440.190 1118.970 ;
        RECT 1.810 1111.130 1440.190 1115.430 ;
      LAYER Pwell ;
        RECT 1.810 1107.590 107.950 1111.130 ;
      LAYER Nwell ;
        RECT 107.950 1107.590 1440.190 1111.130 ;
        RECT 1.810 1103.290 1440.190 1107.590 ;
      LAYER Pwell ;
        RECT 1.810 1099.750 107.950 1103.290 ;
      LAYER Nwell ;
        RECT 107.950 1099.750 1440.190 1103.290 ;
        RECT 1.810 1095.450 1440.190 1099.750 ;
      LAYER Pwell ;
        RECT 1.810 1091.910 107.950 1095.450 ;
      LAYER Nwell ;
        RECT 107.950 1091.910 1440.190 1095.450 ;
        RECT 1.810 1087.610 1440.190 1091.910 ;
      LAYER Pwell ;
        RECT 1.810 1084.070 107.950 1087.610 ;
      LAYER Nwell ;
        RECT 107.950 1084.070 1440.190 1087.610 ;
        RECT 1.810 1079.770 1440.190 1084.070 ;
      LAYER Pwell ;
        RECT 1.810 1076.230 107.950 1079.770 ;
      LAYER Nwell ;
        RECT 107.950 1076.230 1440.190 1079.770 ;
        RECT 1.810 1071.930 1440.190 1076.230 ;
      LAYER Pwell ;
        RECT 1.810 1068.390 107.950 1071.930 ;
      LAYER Nwell ;
        RECT 107.950 1068.390 1440.190 1071.930 ;
        RECT 1.810 1064.090 1440.190 1068.390 ;
      LAYER Pwell ;
        RECT 1.810 1060.550 107.950 1064.090 ;
      LAYER Nwell ;
        RECT 107.950 1060.550 1440.190 1064.090 ;
        RECT 1.810 1056.250 1440.190 1060.550 ;
      LAYER Pwell ;
        RECT 1.810 1052.710 107.950 1056.250 ;
      LAYER Nwell ;
        RECT 107.950 1052.710 1440.190 1056.250 ;
        RECT 1.810 1048.410 1440.190 1052.710 ;
      LAYER Pwell ;
        RECT 1.810 1044.870 107.950 1048.410 ;
      LAYER Nwell ;
        RECT 107.950 1044.870 1440.190 1048.410 ;
        RECT 1.810 1040.570 1440.190 1044.870 ;
      LAYER Pwell ;
        RECT 1.810 1037.030 107.950 1040.570 ;
      LAYER Nwell ;
        RECT 107.950 1037.030 1440.190 1040.570 ;
        RECT 1.810 1032.730 1440.190 1037.030 ;
      LAYER Pwell ;
        RECT 1.810 1029.190 107.950 1032.730 ;
      LAYER Nwell ;
        RECT 107.950 1029.190 1440.190 1032.730 ;
        RECT 1.810 1024.890 1440.190 1029.190 ;
      LAYER Pwell ;
        RECT 1.810 1021.350 107.950 1024.890 ;
      LAYER Nwell ;
        RECT 107.950 1021.350 1440.190 1024.890 ;
        RECT 1.810 1017.050 1440.190 1021.350 ;
      LAYER Pwell ;
        RECT 1.810 1013.510 107.950 1017.050 ;
      LAYER Nwell ;
        RECT 107.950 1013.510 1440.190 1017.050 ;
        RECT 1.810 1009.210 1440.190 1013.510 ;
      LAYER Pwell ;
        RECT 1.810 1005.670 107.950 1009.210 ;
      LAYER Nwell ;
        RECT 107.950 1005.670 1440.190 1009.210 ;
        RECT 1.810 1001.370 1440.190 1005.670 ;
      LAYER Pwell ;
        RECT 1.810 997.830 107.950 1001.370 ;
      LAYER Nwell ;
        RECT 107.950 997.830 1440.190 1001.370 ;
        RECT 1.810 993.530 1440.190 997.830 ;
      LAYER Pwell ;
        RECT 1.810 989.990 107.950 993.530 ;
      LAYER Nwell ;
        RECT 107.950 989.990 1440.190 993.530 ;
        RECT 1.810 985.690 1440.190 989.990 ;
      LAYER Pwell ;
        RECT 1.810 982.150 107.950 985.690 ;
      LAYER Nwell ;
        RECT 107.950 982.150 1440.190 985.690 ;
        RECT 1.810 977.850 1440.190 982.150 ;
      LAYER Pwell ;
        RECT 1.810 974.310 107.950 977.850 ;
      LAYER Nwell ;
        RECT 107.950 974.310 1440.190 977.850 ;
        RECT 1.810 970.010 1440.190 974.310 ;
      LAYER Pwell ;
        RECT 1.810 966.470 107.950 970.010 ;
      LAYER Nwell ;
        RECT 107.950 966.470 1440.190 970.010 ;
        RECT 1.810 962.170 1440.190 966.470 ;
      LAYER Pwell ;
        RECT 1.810 958.630 107.950 962.170 ;
      LAYER Nwell ;
        RECT 107.950 958.630 1440.190 962.170 ;
        RECT 1.810 954.330 1440.190 958.630 ;
      LAYER Pwell ;
        RECT 1.810 950.790 107.950 954.330 ;
      LAYER Nwell ;
        RECT 107.950 950.790 1440.190 954.330 ;
        RECT 1.810 946.490 1440.190 950.790 ;
      LAYER Pwell ;
        RECT 1.810 942.950 107.950 946.490 ;
      LAYER Nwell ;
        RECT 107.950 942.950 1440.190 946.490 ;
        RECT 1.810 938.650 1440.190 942.950 ;
      LAYER Pwell ;
        RECT 1.810 935.110 107.950 938.650 ;
      LAYER Nwell ;
        RECT 107.950 935.110 1440.190 938.650 ;
        RECT 1.810 930.810 1440.190 935.110 ;
      LAYER Pwell ;
        RECT 1.810 927.270 107.950 930.810 ;
      LAYER Nwell ;
        RECT 107.950 927.270 1440.190 930.810 ;
        RECT 1.810 922.970 1440.190 927.270 ;
      LAYER Pwell ;
        RECT 1.810 919.430 107.950 922.970 ;
      LAYER Nwell ;
        RECT 107.950 919.430 1440.190 922.970 ;
        RECT 1.810 915.130 1440.190 919.430 ;
      LAYER Pwell ;
        RECT 1.810 911.590 107.950 915.130 ;
      LAYER Nwell ;
        RECT 107.950 911.590 1440.190 915.130 ;
        RECT 1.810 907.290 1440.190 911.590 ;
      LAYER Pwell ;
        RECT 1.810 903.750 107.950 907.290 ;
      LAYER Nwell ;
        RECT 107.950 903.750 1440.190 907.290 ;
        RECT 1.810 899.450 1440.190 903.750 ;
      LAYER Pwell ;
        RECT 1.810 895.910 107.950 899.450 ;
      LAYER Nwell ;
        RECT 107.950 895.910 1440.190 899.450 ;
        RECT 1.810 891.610 1440.190 895.910 ;
      LAYER Pwell ;
        RECT 1.810 888.070 107.950 891.610 ;
      LAYER Nwell ;
        RECT 107.950 888.070 1440.190 891.610 ;
        RECT 1.810 883.770 1440.190 888.070 ;
      LAYER Pwell ;
        RECT 1.810 880.230 107.950 883.770 ;
      LAYER Nwell ;
        RECT 107.950 880.230 1440.190 883.770 ;
        RECT 1.810 875.930 1440.190 880.230 ;
      LAYER Pwell ;
        RECT 1.810 872.390 107.950 875.930 ;
      LAYER Nwell ;
        RECT 107.950 872.390 1440.190 875.930 ;
        RECT 1.810 868.090 1440.190 872.390 ;
      LAYER Pwell ;
        RECT 1.810 864.550 107.950 868.090 ;
      LAYER Nwell ;
        RECT 107.950 864.550 1440.190 868.090 ;
        RECT 1.810 860.250 1440.190 864.550 ;
      LAYER Pwell ;
        RECT 1.810 856.710 107.950 860.250 ;
      LAYER Nwell ;
        RECT 107.950 856.710 1440.190 860.250 ;
        RECT 1.810 852.410 1440.190 856.710 ;
      LAYER Pwell ;
        RECT 1.810 848.870 107.950 852.410 ;
      LAYER Nwell ;
        RECT 107.950 848.870 1440.190 852.410 ;
        RECT 1.810 844.570 1440.190 848.870 ;
      LAYER Pwell ;
        RECT 1.810 841.030 107.950 844.570 ;
      LAYER Nwell ;
        RECT 107.950 841.030 1440.190 844.570 ;
        RECT 1.810 836.730 1440.190 841.030 ;
      LAYER Pwell ;
        RECT 1.810 833.190 107.950 836.730 ;
      LAYER Nwell ;
        RECT 107.950 833.190 1440.190 836.730 ;
        RECT 1.810 828.890 1440.190 833.190 ;
      LAYER Pwell ;
        RECT 1.810 825.350 107.950 828.890 ;
      LAYER Nwell ;
        RECT 107.950 825.350 1440.190 828.890 ;
        RECT 1.810 821.050 1440.190 825.350 ;
      LAYER Pwell ;
        RECT 1.810 817.510 107.950 821.050 ;
      LAYER Nwell ;
        RECT 107.950 817.510 1440.190 821.050 ;
        RECT 1.810 813.210 1440.190 817.510 ;
      LAYER Pwell ;
        RECT 1.810 809.670 107.950 813.210 ;
      LAYER Nwell ;
        RECT 107.950 809.670 1440.190 813.210 ;
        RECT 1.810 805.370 1440.190 809.670 ;
      LAYER Pwell ;
        RECT 1.810 801.830 107.950 805.370 ;
      LAYER Nwell ;
        RECT 107.950 801.830 1440.190 805.370 ;
        RECT 1.810 797.530 1440.190 801.830 ;
      LAYER Pwell ;
        RECT 1.810 793.990 107.950 797.530 ;
      LAYER Nwell ;
        RECT 107.950 793.990 1440.190 797.530 ;
        RECT 1.810 789.690 1440.190 793.990 ;
      LAYER Pwell ;
        RECT 1.810 786.150 107.950 789.690 ;
      LAYER Nwell ;
        RECT 107.950 786.150 1440.190 789.690 ;
        RECT 1.810 781.850 1440.190 786.150 ;
      LAYER Pwell ;
        RECT 1.810 778.310 107.950 781.850 ;
      LAYER Nwell ;
        RECT 107.950 778.310 1440.190 781.850 ;
        RECT 1.810 774.010 1440.190 778.310 ;
      LAYER Pwell ;
        RECT 1.810 770.470 107.950 774.010 ;
      LAYER Nwell ;
        RECT 107.950 770.470 1440.190 774.010 ;
        RECT 1.810 766.170 1440.190 770.470 ;
      LAYER Pwell ;
        RECT 1.810 762.630 107.950 766.170 ;
      LAYER Nwell ;
        RECT 107.950 762.630 1440.190 766.170 ;
        RECT 1.810 758.330 1440.190 762.630 ;
      LAYER Pwell ;
        RECT 1.810 754.790 107.950 758.330 ;
      LAYER Nwell ;
        RECT 107.950 754.790 1440.190 758.330 ;
        RECT 1.810 750.490 1440.190 754.790 ;
      LAYER Pwell ;
        RECT 1.810 746.950 107.950 750.490 ;
      LAYER Nwell ;
        RECT 107.950 746.950 1440.190 750.490 ;
        RECT 1.810 742.650 1440.190 746.950 ;
      LAYER Pwell ;
        RECT 1.810 739.110 107.950 742.650 ;
      LAYER Nwell ;
        RECT 107.950 739.110 1440.190 742.650 ;
        RECT 1.810 734.810 1440.190 739.110 ;
      LAYER Pwell ;
        RECT 1.810 731.270 107.950 734.810 ;
      LAYER Nwell ;
        RECT 107.950 731.270 1440.190 734.810 ;
        RECT 1.810 726.970 1440.190 731.270 ;
      LAYER Pwell ;
        RECT 1.810 723.430 107.950 726.970 ;
      LAYER Nwell ;
        RECT 107.950 723.430 1440.190 726.970 ;
        RECT 1.810 719.130 1440.190 723.430 ;
      LAYER Pwell ;
        RECT 1.810 715.590 107.950 719.130 ;
      LAYER Nwell ;
        RECT 107.950 715.590 1440.190 719.130 ;
        RECT 1.810 711.290 1440.190 715.590 ;
      LAYER Pwell ;
        RECT 1.810 707.750 107.950 711.290 ;
      LAYER Nwell ;
        RECT 107.950 707.750 1440.190 711.290 ;
        RECT 1.810 703.450 1440.190 707.750 ;
      LAYER Pwell ;
        RECT 1.810 699.910 107.950 703.450 ;
      LAYER Nwell ;
        RECT 107.950 699.910 1440.190 703.450 ;
        RECT 1.810 695.610 1440.190 699.910 ;
      LAYER Pwell ;
        RECT 1.810 692.070 107.950 695.610 ;
      LAYER Nwell ;
        RECT 107.950 692.070 1440.190 695.610 ;
        RECT 1.810 687.770 1440.190 692.070 ;
      LAYER Pwell ;
        RECT 1.810 684.230 107.950 687.770 ;
      LAYER Nwell ;
        RECT 107.950 684.230 1440.190 687.770 ;
        RECT 1.810 679.930 1440.190 684.230 ;
      LAYER Pwell ;
        RECT 1.810 676.390 107.950 679.930 ;
      LAYER Nwell ;
        RECT 107.950 676.390 1440.190 679.930 ;
        RECT 1.810 672.090 1440.190 676.390 ;
      LAYER Pwell ;
        RECT 1.810 668.550 107.950 672.090 ;
      LAYER Nwell ;
        RECT 107.950 668.550 1440.190 672.090 ;
        RECT 1.810 664.250 1440.190 668.550 ;
      LAYER Pwell ;
        RECT 1.810 660.710 107.950 664.250 ;
      LAYER Nwell ;
        RECT 107.950 660.710 1440.190 664.250 ;
        RECT 1.810 656.410 1440.190 660.710 ;
      LAYER Pwell ;
        RECT 1.810 652.870 107.950 656.410 ;
      LAYER Nwell ;
        RECT 107.950 652.870 1440.190 656.410 ;
        RECT 1.810 648.570 1440.190 652.870 ;
      LAYER Pwell ;
        RECT 1.810 645.030 107.950 648.570 ;
      LAYER Nwell ;
        RECT 107.950 645.030 1440.190 648.570 ;
        RECT 1.810 640.730 1440.190 645.030 ;
      LAYER Pwell ;
        RECT 1.810 637.190 107.950 640.730 ;
      LAYER Nwell ;
        RECT 107.950 637.190 1440.190 640.730 ;
        RECT 1.810 632.890 1440.190 637.190 ;
      LAYER Pwell ;
        RECT 1.810 629.350 107.950 632.890 ;
      LAYER Nwell ;
        RECT 107.950 629.350 1440.190 632.890 ;
        RECT 1.810 625.050 1440.190 629.350 ;
      LAYER Pwell ;
        RECT 1.810 621.510 107.950 625.050 ;
      LAYER Nwell ;
        RECT 107.950 621.510 1440.190 625.050 ;
        RECT 1.810 617.210 1440.190 621.510 ;
      LAYER Pwell ;
        RECT 1.810 613.670 107.950 617.210 ;
      LAYER Nwell ;
        RECT 107.950 613.670 1440.190 617.210 ;
        RECT 1.810 609.370 1440.190 613.670 ;
      LAYER Pwell ;
        RECT 1.810 605.830 107.950 609.370 ;
      LAYER Nwell ;
        RECT 107.950 605.830 1440.190 609.370 ;
        RECT 1.810 601.530 1440.190 605.830 ;
      LAYER Pwell ;
        RECT 1.810 597.990 107.950 601.530 ;
      LAYER Nwell ;
        RECT 107.950 597.990 1440.190 601.530 ;
        RECT 1.810 593.690 1440.190 597.990 ;
      LAYER Pwell ;
        RECT 1.810 590.150 107.950 593.690 ;
      LAYER Nwell ;
        RECT 107.950 590.150 1440.190 593.690 ;
        RECT 1.810 585.850 1440.190 590.150 ;
      LAYER Pwell ;
        RECT 1.810 582.310 107.950 585.850 ;
      LAYER Nwell ;
        RECT 107.950 582.310 1440.190 585.850 ;
        RECT 1.810 578.010 1440.190 582.310 ;
      LAYER Pwell ;
        RECT 1.810 574.470 107.950 578.010 ;
      LAYER Nwell ;
        RECT 107.950 574.470 1440.190 578.010 ;
        RECT 1.810 570.170 1440.190 574.470 ;
      LAYER Pwell ;
        RECT 1.810 566.630 107.950 570.170 ;
      LAYER Nwell ;
        RECT 107.950 566.630 1440.190 570.170 ;
        RECT 1.810 562.330 1440.190 566.630 ;
      LAYER Pwell ;
        RECT 1.810 558.790 107.950 562.330 ;
      LAYER Nwell ;
        RECT 107.950 558.790 1440.190 562.330 ;
        RECT 1.810 554.490 1440.190 558.790 ;
      LAYER Pwell ;
        RECT 1.810 550.950 107.950 554.490 ;
      LAYER Nwell ;
        RECT 107.950 550.950 1440.190 554.490 ;
        RECT 1.810 546.650 1440.190 550.950 ;
      LAYER Pwell ;
        RECT 1.810 543.110 107.950 546.650 ;
      LAYER Nwell ;
        RECT 107.950 543.110 1440.190 546.650 ;
        RECT 1.810 538.810 1440.190 543.110 ;
      LAYER Pwell ;
        RECT 1.810 535.270 107.950 538.810 ;
      LAYER Nwell ;
        RECT 107.950 535.270 1440.190 538.810 ;
        RECT 1.810 530.970 1440.190 535.270 ;
      LAYER Pwell ;
        RECT 1.810 527.430 107.950 530.970 ;
      LAYER Nwell ;
        RECT 107.950 527.430 1440.190 530.970 ;
        RECT 1.810 523.130 1440.190 527.430 ;
      LAYER Pwell ;
        RECT 1.810 519.590 107.950 523.130 ;
      LAYER Nwell ;
        RECT 107.950 519.590 1440.190 523.130 ;
        RECT 1.810 515.290 1440.190 519.590 ;
      LAYER Pwell ;
        RECT 1.810 511.750 107.950 515.290 ;
      LAYER Nwell ;
        RECT 107.950 511.750 1440.190 515.290 ;
        RECT 1.810 507.450 1440.190 511.750 ;
      LAYER Pwell ;
        RECT 1.810 503.910 107.950 507.450 ;
      LAYER Nwell ;
        RECT 107.950 503.910 1440.190 507.450 ;
        RECT 1.810 499.610 1440.190 503.910 ;
      LAYER Pwell ;
        RECT 1.810 496.070 107.950 499.610 ;
      LAYER Nwell ;
        RECT 107.950 496.070 1440.190 499.610 ;
        RECT 1.810 491.770 1440.190 496.070 ;
      LAYER Pwell ;
        RECT 1.810 488.230 107.950 491.770 ;
      LAYER Nwell ;
        RECT 107.950 488.230 1440.190 491.770 ;
        RECT 1.810 483.930 1440.190 488.230 ;
      LAYER Pwell ;
        RECT 1.810 480.390 107.950 483.930 ;
      LAYER Nwell ;
        RECT 107.950 480.390 1440.190 483.930 ;
        RECT 1.810 476.090 1440.190 480.390 ;
      LAYER Pwell ;
        RECT 1.810 472.550 107.950 476.090 ;
      LAYER Nwell ;
        RECT 107.950 472.550 1440.190 476.090 ;
        RECT 1.810 468.250 1440.190 472.550 ;
      LAYER Pwell ;
        RECT 1.810 464.710 107.950 468.250 ;
      LAYER Nwell ;
        RECT 107.950 464.710 1440.190 468.250 ;
        RECT 1.810 460.410 1440.190 464.710 ;
      LAYER Pwell ;
        RECT 1.810 456.870 107.950 460.410 ;
      LAYER Nwell ;
        RECT 107.950 456.870 1440.190 460.410 ;
        RECT 1.810 452.570 1440.190 456.870 ;
      LAYER Pwell ;
        RECT 1.810 449.030 107.950 452.570 ;
      LAYER Nwell ;
        RECT 107.950 449.030 1440.190 452.570 ;
        RECT 1.810 444.730 1440.190 449.030 ;
      LAYER Pwell ;
        RECT 1.810 441.190 107.950 444.730 ;
      LAYER Nwell ;
        RECT 107.950 441.190 1440.190 444.730 ;
        RECT 1.810 436.890 1440.190 441.190 ;
      LAYER Pwell ;
        RECT 1.810 433.350 107.950 436.890 ;
      LAYER Nwell ;
        RECT 107.950 433.350 1440.190 436.890 ;
        RECT 1.810 429.050 1440.190 433.350 ;
      LAYER Pwell ;
        RECT 1.810 425.510 107.950 429.050 ;
      LAYER Nwell ;
        RECT 107.950 425.510 1440.190 429.050 ;
        RECT 1.810 421.210 1440.190 425.510 ;
      LAYER Pwell ;
        RECT 1.810 417.670 107.950 421.210 ;
      LAYER Nwell ;
        RECT 107.950 417.670 1440.190 421.210 ;
        RECT 1.810 413.370 1440.190 417.670 ;
      LAYER Pwell ;
        RECT 1.810 409.830 107.950 413.370 ;
      LAYER Nwell ;
        RECT 107.950 409.830 1440.190 413.370 ;
        RECT 1.810 405.530 1440.190 409.830 ;
      LAYER Pwell ;
        RECT 1.810 401.990 107.950 405.530 ;
      LAYER Nwell ;
        RECT 107.950 401.990 1440.190 405.530 ;
        RECT 1.810 397.690 1440.190 401.990 ;
      LAYER Pwell ;
        RECT 1.810 394.150 107.950 397.690 ;
      LAYER Nwell ;
        RECT 107.950 394.150 1440.190 397.690 ;
        RECT 1.810 389.850 1440.190 394.150 ;
      LAYER Pwell ;
        RECT 1.810 386.310 107.950 389.850 ;
      LAYER Nwell ;
        RECT 107.950 386.310 1440.190 389.850 ;
        RECT 1.810 382.010 1440.190 386.310 ;
      LAYER Pwell ;
        RECT 1.810 378.470 107.950 382.010 ;
      LAYER Nwell ;
        RECT 107.950 378.470 1440.190 382.010 ;
        RECT 1.810 374.170 1440.190 378.470 ;
      LAYER Pwell ;
        RECT 1.810 370.630 107.950 374.170 ;
      LAYER Nwell ;
        RECT 107.950 370.630 1440.190 374.170 ;
        RECT 1.810 366.330 1440.190 370.630 ;
      LAYER Pwell ;
        RECT 1.810 362.790 107.950 366.330 ;
      LAYER Nwell ;
        RECT 107.950 362.790 1440.190 366.330 ;
        RECT 1.810 358.490 1440.190 362.790 ;
      LAYER Pwell ;
        RECT 1.810 354.950 107.950 358.490 ;
      LAYER Nwell ;
        RECT 107.950 354.950 1440.190 358.490 ;
        RECT 1.810 350.650 1440.190 354.950 ;
      LAYER Pwell ;
        RECT 1.810 347.110 107.950 350.650 ;
      LAYER Nwell ;
        RECT 107.950 347.110 1440.190 350.650 ;
        RECT 1.810 342.810 1440.190 347.110 ;
      LAYER Pwell ;
        RECT 1.810 339.270 107.950 342.810 ;
      LAYER Nwell ;
        RECT 107.950 339.270 1440.190 342.810 ;
        RECT 1.810 334.970 1440.190 339.270 ;
      LAYER Pwell ;
        RECT 1.810 331.430 107.950 334.970 ;
      LAYER Nwell ;
        RECT 107.950 331.430 1440.190 334.970 ;
        RECT 1.810 327.130 1440.190 331.430 ;
      LAYER Pwell ;
        RECT 1.810 323.590 107.950 327.130 ;
      LAYER Nwell ;
        RECT 107.950 323.590 1440.190 327.130 ;
        RECT 1.810 319.290 1440.190 323.590 ;
      LAYER Pwell ;
        RECT 1.810 315.750 107.950 319.290 ;
      LAYER Nwell ;
        RECT 107.950 315.750 1440.190 319.290 ;
        RECT 1.810 311.450 1440.190 315.750 ;
      LAYER Pwell ;
        RECT 1.810 307.910 107.950 311.450 ;
      LAYER Nwell ;
        RECT 107.950 307.910 1440.190 311.450 ;
        RECT 1.810 303.610 1440.190 307.910 ;
      LAYER Pwell ;
        RECT 1.810 300.070 107.950 303.610 ;
      LAYER Nwell ;
        RECT 107.950 300.070 1440.190 303.610 ;
        RECT 1.810 295.770 1440.190 300.070 ;
      LAYER Pwell ;
        RECT 1.810 292.230 107.950 295.770 ;
      LAYER Nwell ;
        RECT 107.950 292.230 1440.190 295.770 ;
        RECT 1.810 287.930 1440.190 292.230 ;
      LAYER Pwell ;
        RECT 1.810 286.590 107.950 287.930 ;
      LAYER Nwell ;
        RECT 107.950 286.590 1440.190 287.930 ;
      LAYER Pwell ;
        RECT 1.810 284.390 1440.190 286.590 ;
      LAYER Nwell ;
        RECT 1.810 280.090 1440.190 284.390 ;
      LAYER Pwell ;
        RECT 1.810 276.550 1440.190 280.090 ;
      LAYER Nwell ;
        RECT 1.810 272.250 1440.190 276.550 ;
      LAYER Pwell ;
        RECT 1.810 268.710 1440.190 272.250 ;
      LAYER Nwell ;
        RECT 1.810 264.410 1440.190 268.710 ;
      LAYER Pwell ;
        RECT 1.810 260.870 1440.190 264.410 ;
      LAYER Nwell ;
        RECT 1.810 256.570 1440.190 260.870 ;
      LAYER Pwell ;
        RECT 1.810 253.030 1440.190 256.570 ;
      LAYER Nwell ;
        RECT 1.810 248.730 1440.190 253.030 ;
      LAYER Pwell ;
        RECT 1.810 245.190 1440.190 248.730 ;
      LAYER Nwell ;
        RECT 1.810 240.890 1440.190 245.190 ;
      LAYER Pwell ;
        RECT 1.810 237.350 1440.190 240.890 ;
      LAYER Nwell ;
        RECT 1.810 233.050 1440.190 237.350 ;
      LAYER Pwell ;
        RECT 1.810 229.510 107.950 233.050 ;
      LAYER Nwell ;
        RECT 107.950 229.510 1440.190 233.050 ;
        RECT 1.810 225.210 1440.190 229.510 ;
      LAYER Pwell ;
        RECT 1.810 221.670 107.950 225.210 ;
      LAYER Nwell ;
        RECT 107.950 221.670 1440.190 225.210 ;
        RECT 1.810 217.370 1440.190 221.670 ;
      LAYER Pwell ;
        RECT 1.810 213.830 107.950 217.370 ;
      LAYER Nwell ;
        RECT 107.950 213.830 1440.190 217.370 ;
        RECT 1.810 209.530 1440.190 213.830 ;
      LAYER Pwell ;
        RECT 1.810 205.990 107.950 209.530 ;
      LAYER Nwell ;
        RECT 107.950 205.990 1440.190 209.530 ;
        RECT 1.810 201.690 1440.190 205.990 ;
      LAYER Pwell ;
        RECT 1.810 198.150 107.950 201.690 ;
      LAYER Nwell ;
        RECT 107.950 198.150 1440.190 201.690 ;
        RECT 1.810 193.850 1440.190 198.150 ;
      LAYER Pwell ;
        RECT 1.810 190.310 107.950 193.850 ;
      LAYER Nwell ;
        RECT 107.950 190.310 1440.190 193.850 ;
        RECT 1.810 186.010 1440.190 190.310 ;
      LAYER Pwell ;
        RECT 1.810 182.470 107.950 186.010 ;
      LAYER Nwell ;
        RECT 107.950 182.470 1440.190 186.010 ;
        RECT 1.810 178.170 1440.190 182.470 ;
      LAYER Pwell ;
        RECT 1.810 174.630 107.950 178.170 ;
      LAYER Nwell ;
        RECT 107.950 174.630 1440.190 178.170 ;
        RECT 1.810 170.330 1440.190 174.630 ;
      LAYER Pwell ;
        RECT 1.810 166.790 107.950 170.330 ;
      LAYER Nwell ;
        RECT 107.950 166.790 1440.190 170.330 ;
        RECT 1.810 162.490 1440.190 166.790 ;
      LAYER Pwell ;
        RECT 1.810 158.950 107.950 162.490 ;
      LAYER Nwell ;
        RECT 107.950 158.950 1440.190 162.490 ;
        RECT 1.810 154.650 1440.190 158.950 ;
      LAYER Pwell ;
        RECT 1.810 151.110 107.950 154.650 ;
      LAYER Nwell ;
        RECT 107.950 151.110 1440.190 154.650 ;
        RECT 1.810 146.810 1440.190 151.110 ;
      LAYER Pwell ;
        RECT 1.810 143.270 107.950 146.810 ;
      LAYER Nwell ;
        RECT 107.950 143.270 1440.190 146.810 ;
        RECT 1.810 138.970 1440.190 143.270 ;
      LAYER Pwell ;
        RECT 1.810 135.430 107.950 138.970 ;
      LAYER Nwell ;
        RECT 107.950 135.430 1440.190 138.970 ;
        RECT 1.810 131.130 1440.190 135.430 ;
      LAYER Pwell ;
        RECT 1.810 127.590 107.950 131.130 ;
      LAYER Nwell ;
        RECT 107.950 127.590 1440.190 131.130 ;
        RECT 1.810 123.290 1440.190 127.590 ;
      LAYER Pwell ;
        RECT 1.810 119.750 107.950 123.290 ;
      LAYER Nwell ;
        RECT 107.950 119.750 1440.190 123.290 ;
        RECT 1.810 115.450 1440.190 119.750 ;
      LAYER Pwell ;
        RECT 1.810 111.910 107.950 115.450 ;
      LAYER Nwell ;
        RECT 107.950 111.910 1440.190 115.450 ;
        RECT 1.810 107.610 1440.190 111.910 ;
      LAYER Pwell ;
        RECT 1.810 104.070 107.950 107.610 ;
      LAYER Nwell ;
        RECT 107.950 104.070 1440.190 107.610 ;
        RECT 1.810 99.770 1440.190 104.070 ;
      LAYER Pwell ;
        RECT 1.810 96.230 107.950 99.770 ;
      LAYER Nwell ;
        RECT 107.950 96.230 1440.190 99.770 ;
        RECT 1.810 91.930 1440.190 96.230 ;
      LAYER Pwell ;
        RECT 1.810 88.390 107.950 91.930 ;
      LAYER Nwell ;
        RECT 107.950 88.390 1440.190 91.930 ;
        RECT 1.810 84.090 1440.190 88.390 ;
      LAYER Pwell ;
        RECT 1.810 80.550 107.950 84.090 ;
      LAYER Nwell ;
        RECT 107.950 80.550 1440.190 84.090 ;
        RECT 1.810 76.250 1440.190 80.550 ;
      LAYER Pwell ;
        RECT 1.810 72.710 107.950 76.250 ;
      LAYER Nwell ;
        RECT 107.950 72.710 1440.190 76.250 ;
        RECT 1.810 68.410 1440.190 72.710 ;
      LAYER Pwell ;
        RECT 1.810 64.870 107.950 68.410 ;
      LAYER Nwell ;
        RECT 107.950 64.870 1440.190 68.410 ;
        RECT 1.810 60.570 1440.190 64.870 ;
      LAYER Pwell ;
        RECT 1.810 57.030 107.950 60.570 ;
      LAYER Nwell ;
        RECT 107.950 57.030 1440.190 60.570 ;
        RECT 1.810 52.730 1440.190 57.030 ;
      LAYER Pwell ;
        RECT 1.810 49.190 107.950 52.730 ;
      LAYER Nwell ;
        RECT 107.950 49.190 1440.190 52.730 ;
        RECT 1.810 44.890 1440.190 49.190 ;
      LAYER Pwell ;
        RECT 1.810 41.350 107.950 44.890 ;
      LAYER Nwell ;
        RECT 107.950 41.350 1440.190 44.890 ;
        RECT 1.810 37.050 1440.190 41.350 ;
      LAYER Pwell ;
        RECT 1.810 33.510 107.950 37.050 ;
      LAYER Nwell ;
        RECT 107.950 33.510 1440.190 37.050 ;
        RECT 1.810 29.210 1440.190 33.510 ;
      LAYER Pwell ;
        RECT 1.810 25.670 107.950 29.210 ;
      LAYER Nwell ;
        RECT 107.950 25.670 1440.190 29.210 ;
        RECT 1.810 21.370 1440.190 25.670 ;
      LAYER Pwell ;
        RECT 1.810 17.830 107.950 21.370 ;
      LAYER Nwell ;
        RECT 107.950 17.830 1440.190 21.370 ;
        RECT 1.810 13.530 1440.190 17.830 ;
      LAYER Pwell ;
        RECT 1.810 9.990 107.950 13.530 ;
      LAYER Nwell ;
        RECT 107.950 9.990 1440.190 13.530 ;
        RECT 1.810 5.690 1440.190 9.990 ;
      LAYER Pwell ;
        RECT 1.810 3.490 107.950 5.690 ;
      LAYER Nwell ;
        RECT 107.950 3.490 1440.190 5.690 ;
      LAYER Metal1 ;
        RECT 2.240 3.620 1439.760 1556.540 ;
      LAYER Metal2 ;
        RECT 3.500 3.730 1428.580 1559.510 ;
      LAYER Metal3 ;
        RECT 3.450 3.780 1428.630 1559.460 ;
      LAYER Metal4 ;
        RECT 14.700 1558.860 32.310 1559.160 ;
        RECT 33.210 1558.860 39.590 1559.160 ;
        RECT 40.490 1558.860 46.870 1559.160 ;
        RECT 47.770 1558.860 54.150 1559.160 ;
        RECT 55.050 1558.860 61.430 1559.160 ;
        RECT 62.330 1558.860 68.710 1559.160 ;
        RECT 69.610 1558.860 75.990 1559.160 ;
        RECT 76.890 1558.860 83.270 1559.160 ;
        RECT 84.170 1558.860 90.550 1559.160 ;
        RECT 91.450 1558.860 97.830 1559.160 ;
        RECT 98.730 1558.860 105.110 1559.160 ;
        RECT 106.010 1558.860 112.390 1559.160 ;
        RECT 113.290 1558.860 119.670 1559.160 ;
        RECT 120.570 1558.860 126.950 1559.160 ;
        RECT 127.850 1558.860 134.230 1559.160 ;
        RECT 135.130 1558.860 141.510 1559.160 ;
        RECT 142.410 1558.860 148.790 1559.160 ;
        RECT 149.690 1558.860 156.070 1559.160 ;
        RECT 156.970 1558.860 163.350 1559.160 ;
        RECT 164.250 1558.860 170.630 1559.160 ;
        RECT 171.530 1558.860 177.910 1559.160 ;
        RECT 178.810 1558.860 185.190 1559.160 ;
        RECT 186.090 1558.860 192.470 1559.160 ;
        RECT 193.370 1558.860 199.750 1559.160 ;
        RECT 200.650 1558.860 207.030 1559.160 ;
        RECT 207.930 1558.860 214.310 1559.160 ;
        RECT 215.210 1558.860 221.590 1559.160 ;
        RECT 222.490 1558.860 228.870 1559.160 ;
        RECT 229.770 1558.860 236.150 1559.160 ;
        RECT 237.050 1558.860 243.430 1559.160 ;
        RECT 244.330 1558.860 250.710 1559.160 ;
        RECT 251.610 1558.860 257.990 1559.160 ;
        RECT 258.890 1558.860 265.270 1559.160 ;
        RECT 266.170 1558.860 272.550 1559.160 ;
        RECT 273.450 1558.860 279.830 1559.160 ;
        RECT 280.730 1558.860 287.110 1559.160 ;
        RECT 288.010 1558.860 294.390 1559.160 ;
        RECT 295.290 1558.860 301.670 1559.160 ;
        RECT 302.570 1558.860 308.950 1559.160 ;
        RECT 309.850 1558.860 316.230 1559.160 ;
        RECT 317.130 1558.860 323.510 1559.160 ;
        RECT 324.410 1558.860 330.790 1559.160 ;
        RECT 331.690 1558.860 338.070 1559.160 ;
        RECT 338.970 1558.860 1369.060 1559.160 ;
        RECT 14.700 1556.840 1369.060 1558.860 ;
        RECT 14.700 244.810 20.340 1556.840 ;
        RECT 24.140 244.810 25.240 1556.840 ;
        RECT 29.040 244.810 70.340 1556.840 ;
        RECT 74.140 244.810 75.240 1556.840 ;
        RECT 79.040 1481.650 120.340 1556.840 ;
        RECT 124.140 1481.650 125.240 1556.840 ;
        RECT 129.040 1481.650 170.340 1556.840 ;
        RECT 174.140 1481.650 175.240 1556.840 ;
        RECT 179.040 1481.650 220.340 1556.840 ;
        RECT 224.140 1481.650 225.240 1556.840 ;
        RECT 229.040 1481.650 270.340 1556.840 ;
        RECT 274.140 1481.650 275.240 1556.840 ;
        RECT 279.040 1481.650 320.340 1556.840 ;
        RECT 324.140 1481.650 325.240 1556.840 ;
        RECT 329.040 1481.650 370.340 1556.840 ;
        RECT 374.140 1481.650 375.240 1556.840 ;
        RECT 379.040 1481.650 420.340 1556.840 ;
        RECT 424.140 1481.650 425.240 1556.840 ;
        RECT 429.040 1481.650 470.340 1556.840 ;
        RECT 474.140 1481.650 475.240 1556.840 ;
        RECT 479.040 1481.650 520.340 1556.840 ;
        RECT 524.140 1481.650 525.240 1556.840 ;
        RECT 529.040 1481.650 570.340 1556.840 ;
        RECT 574.140 1481.650 575.240 1556.840 ;
        RECT 579.040 1481.650 620.340 1556.840 ;
        RECT 624.140 1481.650 625.240 1556.840 ;
        RECT 629.040 1481.650 670.340 1556.840 ;
        RECT 674.140 1481.650 675.240 1556.840 ;
        RECT 679.040 1481.650 720.340 1556.840 ;
        RECT 724.140 1481.650 725.240 1556.840 ;
        RECT 729.040 1481.650 770.340 1556.840 ;
        RECT 774.140 1481.650 775.240 1556.840 ;
        RECT 779.040 1481.650 820.340 1556.840 ;
        RECT 824.140 1481.650 825.240 1556.840 ;
        RECT 829.040 1481.650 870.340 1556.840 ;
        RECT 874.140 1481.650 875.240 1556.840 ;
        RECT 879.040 1481.650 920.340 1556.840 ;
        RECT 924.140 1481.650 925.240 1556.840 ;
        RECT 929.040 1481.650 970.340 1556.840 ;
        RECT 974.140 1481.650 975.240 1556.840 ;
        RECT 979.040 1481.650 1020.340 1556.840 ;
        RECT 1024.140 1481.650 1025.240 1556.840 ;
        RECT 1029.040 1481.650 1070.340 1556.840 ;
        RECT 1074.140 1481.650 1075.240 1556.840 ;
        RECT 1079.040 1481.650 1120.340 1556.840 ;
        RECT 1124.140 1481.650 1125.240 1556.840 ;
        RECT 1129.040 1481.650 1170.340 1556.840 ;
        RECT 1174.140 1481.650 1175.240 1556.840 ;
        RECT 1179.040 1481.650 1220.340 1556.840 ;
        RECT 1224.140 1481.650 1225.240 1556.840 ;
        RECT 1229.040 1481.650 1270.340 1556.840 ;
        RECT 1274.140 1481.650 1275.240 1556.840 ;
        RECT 1279.040 1481.650 1320.340 1556.840 ;
        RECT 1324.140 1481.650 1325.240 1556.840 ;
        RECT 1329.040 1481.650 1369.060 1556.840 ;
        RECT 79.040 1478.140 1369.060 1481.650 ;
        RECT 79.040 293.700 130.580 1478.140 ;
        RECT 132.780 293.700 133.880 1478.140 ;
        RECT 136.080 293.700 206.180 1478.140 ;
        RECT 208.380 293.700 209.480 1478.140 ;
        RECT 211.680 293.700 306.180 1478.140 ;
        RECT 308.380 293.700 309.480 1478.140 ;
        RECT 311.680 293.700 406.180 1478.140 ;
        RECT 408.380 293.700 409.480 1478.140 ;
        RECT 411.680 293.700 482.820 1478.140 ;
        RECT 485.020 293.700 486.120 1478.140 ;
        RECT 488.320 293.700 582.820 1478.140 ;
        RECT 585.020 293.700 586.120 1478.140 ;
        RECT 588.320 293.700 682.820 1478.140 ;
        RECT 685.020 293.700 686.120 1478.140 ;
        RECT 688.320 293.700 759.460 1478.140 ;
        RECT 761.660 293.700 762.760 1478.140 ;
        RECT 764.960 293.700 859.460 1478.140 ;
        RECT 861.660 293.700 862.760 1478.140 ;
        RECT 864.960 293.700 959.460 1478.140 ;
        RECT 961.660 293.700 962.760 1478.140 ;
        RECT 964.960 293.700 1036.100 1478.140 ;
        RECT 1038.300 293.700 1039.400 1478.140 ;
        RECT 1041.600 293.700 1136.100 1478.140 ;
        RECT 1138.300 293.700 1139.400 1478.140 ;
        RECT 1141.600 293.700 1236.100 1478.140 ;
        RECT 1238.300 293.700 1239.400 1478.140 ;
        RECT 1241.600 293.700 1312.740 1478.140 ;
        RECT 1314.940 293.700 1316.040 1478.140 ;
        RECT 1318.240 293.700 1369.060 1478.140 ;
        RECT 79.040 290.190 1369.060 293.700 ;
        RECT 79.040 244.810 120.340 290.190 ;
        RECT 124.140 244.810 125.240 290.190 ;
        RECT 129.040 244.810 170.340 290.190 ;
        RECT 174.140 244.810 175.240 290.190 ;
        RECT 179.040 244.810 220.340 290.190 ;
        RECT 224.140 244.810 225.240 290.190 ;
        RECT 229.040 244.810 270.340 290.190 ;
        RECT 274.140 244.810 275.240 290.190 ;
        RECT 279.040 244.810 320.340 290.190 ;
        RECT 324.140 244.810 325.240 290.190 ;
        RECT 329.040 244.810 370.340 290.190 ;
        RECT 374.140 244.810 375.240 290.190 ;
        RECT 379.040 244.810 420.340 290.190 ;
        RECT 424.140 244.810 425.240 290.190 ;
        RECT 429.040 244.810 470.340 290.190 ;
        RECT 474.140 244.810 475.240 290.190 ;
        RECT 479.040 244.810 520.340 290.190 ;
        RECT 524.140 244.810 525.240 290.190 ;
        RECT 529.040 244.810 570.340 290.190 ;
        RECT 574.140 244.810 575.240 290.190 ;
        RECT 579.040 244.810 620.340 290.190 ;
        RECT 624.140 244.810 625.240 290.190 ;
        RECT 629.040 244.810 670.340 290.190 ;
        RECT 674.140 244.810 675.240 290.190 ;
        RECT 679.040 244.810 720.340 290.190 ;
        RECT 724.140 244.810 725.240 290.190 ;
        RECT 729.040 244.810 770.340 290.190 ;
        RECT 774.140 244.810 775.240 290.190 ;
        RECT 779.040 244.810 820.340 290.190 ;
        RECT 824.140 244.810 825.240 290.190 ;
        RECT 829.040 244.810 870.340 290.190 ;
        RECT 874.140 244.810 875.240 290.190 ;
        RECT 879.040 244.810 920.340 290.190 ;
        RECT 924.140 244.810 925.240 290.190 ;
        RECT 929.040 244.810 970.340 290.190 ;
        RECT 974.140 244.810 975.240 290.190 ;
        RECT 979.040 244.810 1020.340 290.190 ;
        RECT 1024.140 244.810 1025.240 290.190 ;
        RECT 1029.040 244.810 1070.340 290.190 ;
        RECT 1074.140 244.810 1075.240 290.190 ;
        RECT 1079.040 244.810 1120.340 290.190 ;
        RECT 1124.140 244.810 1125.240 290.190 ;
        RECT 1129.040 244.810 1170.340 290.190 ;
        RECT 1174.140 244.810 1175.240 290.190 ;
        RECT 1179.040 244.810 1220.340 290.190 ;
        RECT 1224.140 244.810 1225.240 290.190 ;
        RECT 1229.040 244.810 1270.340 290.190 ;
        RECT 1274.140 244.810 1275.240 290.190 ;
        RECT 1279.040 244.810 1320.340 290.190 ;
        RECT 1324.140 244.810 1325.240 290.190 ;
        RECT 1329.040 244.810 1369.060 290.190 ;
  END
END tt_um_fabulous_boat_26
END LIBRARY

